# Generated by FakeRAM 2.0
VERSION 5.7 ;
BUSBITCHARS "[]" ;
PROPERTYDEFINITIONS
  MACRO width INTEGER ;
  MACRO depth INTEGER ;
  MACRO banks INTEGER ;
END PROPERTYDEFINITIONS
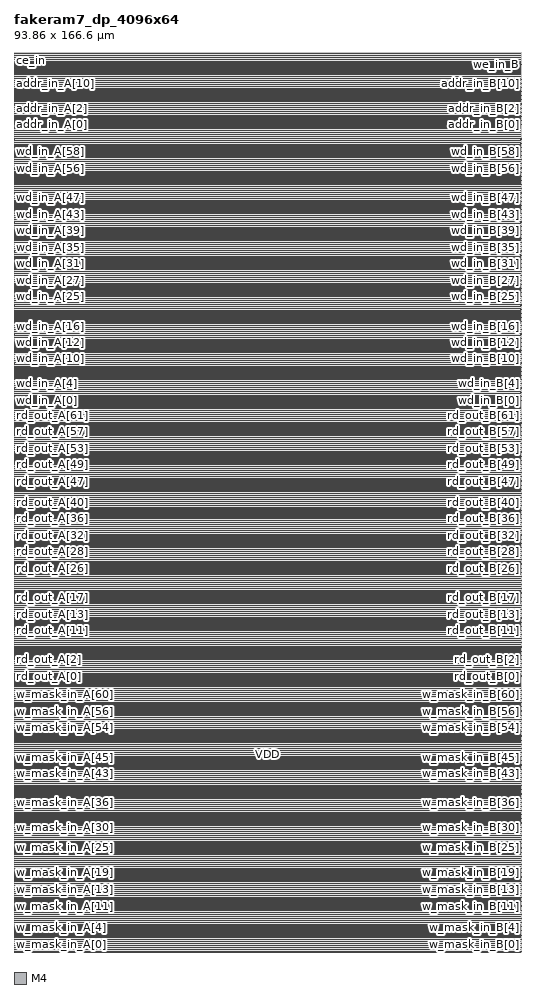
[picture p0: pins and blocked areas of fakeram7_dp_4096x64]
MACRO fakeram7_dp_4096x64
  PROPERTY width 64 ;
  PROPERTY depth 4096 ;
  PROPERTY banks 8 ;
  FOREIGN fakeram7_dp_4096x64 0 0 ;
  SYMMETRY X Y ;
  SIZE 93.860 BY 166.600 ;
  CLASS BLOCK ;
  PIN w_mask_in_A[0]
    DIRECTION INPUT ;
    USE SIGNAL ;
    SHAPE ABUTMENT ;
    PORT
      LAYER M4 ;
      RECT 0.000 0.048 0.024 0.072 ;
    END
  END w_mask_in_A[0]
  PIN w_mask_in_B[0]
    DIRECTION INPUT ;
    USE SIGNAL ;
    SHAPE ABUTMENT ;
    PORT
      LAYER M4 ;
      RECT 93.836 0.048 93.860 0.072 ;
    END
  END w_mask_in_B[0]
  PIN w_mask_in_A[1]
    DIRECTION INPUT ;
    USE SIGNAL ;
    SHAPE ABUTMENT ;
    PORT
      LAYER M4 ;
      RECT 0.000 0.816 0.024 0.840 ;
    END
  END w_mask_in_A[1]
  PIN w_mask_in_B[1]
    DIRECTION INPUT ;
    USE SIGNAL ;
    SHAPE ABUTMENT ;
    PORT
      LAYER M4 ;
      RECT 93.836 0.816 93.860 0.840 ;
    END
  END w_mask_in_B[1]
  PIN w_mask_in_A[2]
    DIRECTION INPUT ;
    USE SIGNAL ;
    SHAPE ABUTMENT ;
    PORT
      LAYER M4 ;
      RECT 0.000 1.584 0.024 1.608 ;
    END
  END w_mask_in_A[2]
  PIN w_mask_in_B[2]
    DIRECTION INPUT ;
    USE SIGNAL ;
    SHAPE ABUTMENT ;
    PORT
      LAYER M4 ;
      RECT 93.836 1.584 93.860 1.608 ;
    END
  END w_mask_in_B[2]
  PIN w_mask_in_A[3]
    DIRECTION INPUT ;
    USE SIGNAL ;
    SHAPE ABUTMENT ;
    PORT
      LAYER M4 ;
      RECT 0.000 2.352 0.024 2.376 ;
    END
  END w_mask_in_A[3]
  PIN w_mask_in_B[3]
    DIRECTION INPUT ;
    USE SIGNAL ;
    SHAPE ABUTMENT ;
    PORT
      LAYER M4 ;
      RECT 93.836 2.352 93.860 2.376 ;
    END
  END w_mask_in_B[3]
  PIN w_mask_in_A[4]
    DIRECTION INPUT ;
    USE SIGNAL ;
    SHAPE ABUTMENT ;
    PORT
      LAYER M4 ;
      RECT 0.000 3.120 0.024 3.144 ;
    END
  END w_mask_in_A[4]
  PIN w_mask_in_B[4]
    DIRECTION INPUT ;
    USE SIGNAL ;
    SHAPE ABUTMENT ;
    PORT
      LAYER M4 ;
      RECT 93.836 3.120 93.860 3.144 ;
    END
  END w_mask_in_B[4]
  PIN w_mask_in_A[5]
    DIRECTION INPUT ;
    USE SIGNAL ;
    SHAPE ABUTMENT ;
    PORT
      LAYER M4 ;
      RECT 0.000 3.888 0.024 3.912 ;
    END
  END w_mask_in_A[5]
  PIN w_mask_in_B[5]
    DIRECTION INPUT ;
    USE SIGNAL ;
    SHAPE ABUTMENT ;
    PORT
      LAYER M4 ;
      RECT 93.836 3.888 93.860 3.912 ;
    END
  END w_mask_in_B[5]
  PIN w_mask_in_A[6]
    DIRECTION INPUT ;
    USE SIGNAL ;
    SHAPE ABUTMENT ;
    PORT
      LAYER M4 ;
      RECT 0.000 4.656 0.024 4.680 ;
    END
  END w_mask_in_A[6]
  PIN w_mask_in_B[6]
    DIRECTION INPUT ;
    USE SIGNAL ;
    SHAPE ABUTMENT ;
    PORT
      LAYER M4 ;
      RECT 93.836 4.656 93.860 4.680 ;
    END
  END w_mask_in_B[6]
  PIN w_mask_in_A[7]
    DIRECTION INPUT ;
    USE SIGNAL ;
    SHAPE ABUTMENT ;
    PORT
      LAYER M4 ;
      RECT 0.000 5.424 0.024 5.448 ;
    END
  END w_mask_in_A[7]
  PIN w_mask_in_B[7]
    DIRECTION INPUT ;
    USE SIGNAL ;
    SHAPE ABUTMENT ;
    PORT
      LAYER M4 ;
      RECT 93.836 5.424 93.860 5.448 ;
    END
  END w_mask_in_B[7]
  PIN w_mask_in_A[8]
    DIRECTION INPUT ;
    USE SIGNAL ;
    SHAPE ABUTMENT ;
    PORT
      LAYER M4 ;
      RECT 0.000 6.192 0.024 6.216 ;
    END
  END w_mask_in_A[8]
  PIN w_mask_in_B[8]
    DIRECTION INPUT ;
    USE SIGNAL ;
    SHAPE ABUTMENT ;
    PORT
      LAYER M4 ;
      RECT 93.836 6.192 93.860 6.216 ;
    END
  END w_mask_in_B[8]
  PIN w_mask_in_A[9]
    DIRECTION INPUT ;
    USE SIGNAL ;
    SHAPE ABUTMENT ;
    PORT
      LAYER M4 ;
      RECT 0.000 6.960 0.024 6.984 ;
    END
  END w_mask_in_A[9]
  PIN w_mask_in_B[9]
    DIRECTION INPUT ;
    USE SIGNAL ;
    SHAPE ABUTMENT ;
    PORT
      LAYER M4 ;
      RECT 93.836 6.960 93.860 6.984 ;
    END
  END w_mask_in_B[9]
  PIN w_mask_in_A[10]
    DIRECTION INPUT ;
    USE SIGNAL ;
    SHAPE ABUTMENT ;
    PORT
      LAYER M4 ;
      RECT 0.000 7.728 0.024 7.752 ;
    END
  END w_mask_in_A[10]
  PIN w_mask_in_B[10]
    DIRECTION INPUT ;
    USE SIGNAL ;
    SHAPE ABUTMENT ;
    PORT
      LAYER M4 ;
      RECT 93.836 7.728 93.860 7.752 ;
    END
  END w_mask_in_B[10]
  PIN w_mask_in_A[11]
    DIRECTION INPUT ;
    USE SIGNAL ;
    SHAPE ABUTMENT ;
    PORT
      LAYER M4 ;
      RECT 0.000 8.496 0.024 8.520 ;
    END
  END w_mask_in_A[11]
  PIN w_mask_in_B[11]
    DIRECTION INPUT ;
    USE SIGNAL ;
    SHAPE ABUTMENT ;
    PORT
      LAYER M4 ;
      RECT 93.836 8.496 93.860 8.520 ;
    END
  END w_mask_in_B[11]
  PIN w_mask_in_A[12]
    DIRECTION INPUT ;
    USE SIGNAL ;
    SHAPE ABUTMENT ;
    PORT
      LAYER M4 ;
      RECT 0.000 9.264 0.024 9.288 ;
    END
  END w_mask_in_A[12]
  PIN w_mask_in_B[12]
    DIRECTION INPUT ;
    USE SIGNAL ;
    SHAPE ABUTMENT ;
    PORT
      LAYER M4 ;
      RECT 93.836 9.264 93.860 9.288 ;
    END
  END w_mask_in_B[12]
  PIN w_mask_in_A[13]
    DIRECTION INPUT ;
    USE SIGNAL ;
    SHAPE ABUTMENT ;
    PORT
      LAYER M4 ;
      RECT 0.000 10.032 0.024 10.056 ;
    END
  END w_mask_in_A[13]
  PIN w_mask_in_B[13]
    DIRECTION INPUT ;
    USE SIGNAL ;
    SHAPE ABUTMENT ;
    PORT
      LAYER M4 ;
      RECT 93.836 10.032 93.860 10.056 ;
    END
  END w_mask_in_B[13]
  PIN w_mask_in_A[14]
    DIRECTION INPUT ;
    USE SIGNAL ;
    SHAPE ABUTMENT ;
    PORT
      LAYER M4 ;
      RECT 0.000 10.800 0.024 10.824 ;
    END
  END w_mask_in_A[14]
  PIN w_mask_in_B[14]
    DIRECTION INPUT ;
    USE SIGNAL ;
    SHAPE ABUTMENT ;
    PORT
      LAYER M4 ;
      RECT 93.836 10.800 93.860 10.824 ;
    END
  END w_mask_in_B[14]
  PIN w_mask_in_A[15]
    DIRECTION INPUT ;
    USE SIGNAL ;
    SHAPE ABUTMENT ;
    PORT
      LAYER M4 ;
      RECT 0.000 11.568 0.024 11.592 ;
    END
  END w_mask_in_A[15]
  PIN w_mask_in_B[15]
    DIRECTION INPUT ;
    USE SIGNAL ;
    SHAPE ABUTMENT ;
    PORT
      LAYER M4 ;
      RECT 93.836 11.568 93.860 11.592 ;
    END
  END w_mask_in_B[15]
  PIN w_mask_in_A[16]
    DIRECTION INPUT ;
    USE SIGNAL ;
    SHAPE ABUTMENT ;
    PORT
      LAYER M4 ;
      RECT 0.000 12.336 0.024 12.360 ;
    END
  END w_mask_in_A[16]
  PIN w_mask_in_B[16]
    DIRECTION INPUT ;
    USE SIGNAL ;
    SHAPE ABUTMENT ;
    PORT
      LAYER M4 ;
      RECT 93.836 12.336 93.860 12.360 ;
    END
  END w_mask_in_B[16]
  PIN w_mask_in_A[17]
    DIRECTION INPUT ;
    USE SIGNAL ;
    SHAPE ABUTMENT ;
    PORT
      LAYER M4 ;
      RECT 0.000 13.104 0.024 13.128 ;
    END
  END w_mask_in_A[17]
  PIN w_mask_in_B[17]
    DIRECTION INPUT ;
    USE SIGNAL ;
    SHAPE ABUTMENT ;
    PORT
      LAYER M4 ;
      RECT 93.836 13.104 93.860 13.128 ;
    END
  END w_mask_in_B[17]
  PIN w_mask_in_A[18]
    DIRECTION INPUT ;
    USE SIGNAL ;
    SHAPE ABUTMENT ;
    PORT
      LAYER M4 ;
      RECT 0.000 13.872 0.024 13.896 ;
    END
  END w_mask_in_A[18]
  PIN w_mask_in_B[18]
    DIRECTION INPUT ;
    USE SIGNAL ;
    SHAPE ABUTMENT ;
    PORT
      LAYER M4 ;
      RECT 93.836 13.872 93.860 13.896 ;
    END
  END w_mask_in_B[18]
  PIN w_mask_in_A[19]
    DIRECTION INPUT ;
    USE SIGNAL ;
    SHAPE ABUTMENT ;
    PORT
      LAYER M4 ;
      RECT 0.000 14.640 0.024 14.664 ;
    END
  END w_mask_in_A[19]
  PIN w_mask_in_B[19]
    DIRECTION INPUT ;
    USE SIGNAL ;
    SHAPE ABUTMENT ;
    PORT
      LAYER M4 ;
      RECT 93.836 14.640 93.860 14.664 ;
    END
  END w_mask_in_B[19]
  PIN w_mask_in_A[20]
    DIRECTION INPUT ;
    USE SIGNAL ;
    SHAPE ABUTMENT ;
    PORT
      LAYER M4 ;
      RECT 0.000 15.408 0.024 15.432 ;
    END
  END w_mask_in_A[20]
  PIN w_mask_in_B[20]
    DIRECTION INPUT ;
    USE SIGNAL ;
    SHAPE ABUTMENT ;
    PORT
      LAYER M4 ;
      RECT 93.836 15.408 93.860 15.432 ;
    END
  END w_mask_in_B[20]
  PIN w_mask_in_A[21]
    DIRECTION INPUT ;
    USE SIGNAL ;
    SHAPE ABUTMENT ;
    PORT
      LAYER M4 ;
      RECT 0.000 16.176 0.024 16.200 ;
    END
  END w_mask_in_A[21]
  PIN w_mask_in_B[21]
    DIRECTION INPUT ;
    USE SIGNAL ;
    SHAPE ABUTMENT ;
    PORT
      LAYER M4 ;
      RECT 93.836 16.176 93.860 16.200 ;
    END
  END w_mask_in_B[21]
  PIN w_mask_in_A[22]
    DIRECTION INPUT ;
    USE SIGNAL ;
    SHAPE ABUTMENT ;
    PORT
      LAYER M4 ;
      RECT 0.000 16.944 0.024 16.968 ;
    END
  END w_mask_in_A[22]
  PIN w_mask_in_B[22]
    DIRECTION INPUT ;
    USE SIGNAL ;
    SHAPE ABUTMENT ;
    PORT
      LAYER M4 ;
      RECT 93.836 16.944 93.860 16.968 ;
    END
  END w_mask_in_B[22]
  PIN w_mask_in_A[23]
    DIRECTION INPUT ;
    USE SIGNAL ;
    SHAPE ABUTMENT ;
    PORT
      LAYER M4 ;
      RECT 0.000 17.712 0.024 17.736 ;
    END
  END w_mask_in_A[23]
  PIN w_mask_in_B[23]
    DIRECTION INPUT ;
    USE SIGNAL ;
    SHAPE ABUTMENT ;
    PORT
      LAYER M4 ;
      RECT 93.836 17.712 93.860 17.736 ;
    END
  END w_mask_in_B[23]
  PIN w_mask_in_A[24]
    DIRECTION INPUT ;
    USE SIGNAL ;
    SHAPE ABUTMENT ;
    PORT
      LAYER M4 ;
      RECT 0.000 18.480 0.024 18.504 ;
    END
  END w_mask_in_A[24]
  PIN w_mask_in_B[24]
    DIRECTION INPUT ;
    USE SIGNAL ;
    SHAPE ABUTMENT ;
    PORT
      LAYER M4 ;
      RECT 93.836 18.480 93.860 18.504 ;
    END
  END w_mask_in_B[24]
  PIN w_mask_in_A[25]
    DIRECTION INPUT ;
    USE SIGNAL ;
    SHAPE ABUTMENT ;
    PORT
      LAYER M4 ;
      RECT 0.000 19.248 0.024 19.272 ;
    END
  END w_mask_in_A[25]
  PIN w_mask_in_B[25]
    DIRECTION INPUT ;
    USE SIGNAL ;
    SHAPE ABUTMENT ;
    PORT
      LAYER M4 ;
      RECT 93.836 19.248 93.860 19.272 ;
    END
  END w_mask_in_B[25]
  PIN w_mask_in_A[26]
    DIRECTION INPUT ;
    USE SIGNAL ;
    SHAPE ABUTMENT ;
    PORT
      LAYER M4 ;
      RECT 0.000 20.016 0.024 20.040 ;
    END
  END w_mask_in_A[26]
  PIN w_mask_in_B[26]
    DIRECTION INPUT ;
    USE SIGNAL ;
    SHAPE ABUTMENT ;
    PORT
      LAYER M4 ;
      RECT 93.836 20.016 93.860 20.040 ;
    END
  END w_mask_in_B[26]
  PIN w_mask_in_A[27]
    DIRECTION INPUT ;
    USE SIGNAL ;
    SHAPE ABUTMENT ;
    PORT
      LAYER M4 ;
      RECT 0.000 20.784 0.024 20.808 ;
    END
  END w_mask_in_A[27]
  PIN w_mask_in_B[27]
    DIRECTION INPUT ;
    USE SIGNAL ;
    SHAPE ABUTMENT ;
    PORT
      LAYER M4 ;
      RECT 93.836 20.784 93.860 20.808 ;
    END
  END w_mask_in_B[27]
  PIN w_mask_in_A[28]
    DIRECTION INPUT ;
    USE SIGNAL ;
    SHAPE ABUTMENT ;
    PORT
      LAYER M4 ;
      RECT 0.000 21.552 0.024 21.576 ;
    END
  END w_mask_in_A[28]
  PIN w_mask_in_B[28]
    DIRECTION INPUT ;
    USE SIGNAL ;
    SHAPE ABUTMENT ;
    PORT
      LAYER M4 ;
      RECT 93.836 21.552 93.860 21.576 ;
    END
  END w_mask_in_B[28]
  PIN w_mask_in_A[29]
    DIRECTION INPUT ;
    USE SIGNAL ;
    SHAPE ABUTMENT ;
    PORT
      LAYER M4 ;
      RECT 0.000 22.320 0.024 22.344 ;
    END
  END w_mask_in_A[29]
  PIN w_mask_in_B[29]
    DIRECTION INPUT ;
    USE SIGNAL ;
    SHAPE ABUTMENT ;
    PORT
      LAYER M4 ;
      RECT 93.836 22.320 93.860 22.344 ;
    END
  END w_mask_in_B[29]
  PIN w_mask_in_A[30]
    DIRECTION INPUT ;
    USE SIGNAL ;
    SHAPE ABUTMENT ;
    PORT
      LAYER M4 ;
      RECT 0.000 23.088 0.024 23.112 ;
    END
  END w_mask_in_A[30]
  PIN w_mask_in_B[30]
    DIRECTION INPUT ;
    USE SIGNAL ;
    SHAPE ABUTMENT ;
    PORT
      LAYER M4 ;
      RECT 93.836 23.088 93.860 23.112 ;
    END
  END w_mask_in_B[30]
  PIN w_mask_in_A[31]
    DIRECTION INPUT ;
    USE SIGNAL ;
    SHAPE ABUTMENT ;
    PORT
      LAYER M4 ;
      RECT 0.000 23.856 0.024 23.880 ;
    END
  END w_mask_in_A[31]
  PIN w_mask_in_B[31]
    DIRECTION INPUT ;
    USE SIGNAL ;
    SHAPE ABUTMENT ;
    PORT
      LAYER M4 ;
      RECT 93.836 23.856 93.860 23.880 ;
    END
  END w_mask_in_B[31]
  PIN w_mask_in_A[32]
    DIRECTION INPUT ;
    USE SIGNAL ;
    SHAPE ABUTMENT ;
    PORT
      LAYER M4 ;
      RECT 0.000 24.624 0.024 24.648 ;
    END
  END w_mask_in_A[32]
  PIN w_mask_in_B[32]
    DIRECTION INPUT ;
    USE SIGNAL ;
    SHAPE ABUTMENT ;
    PORT
      LAYER M4 ;
      RECT 93.836 24.624 93.860 24.648 ;
    END
  END w_mask_in_B[32]
  PIN w_mask_in_A[33]
    DIRECTION INPUT ;
    USE SIGNAL ;
    SHAPE ABUTMENT ;
    PORT
      LAYER M4 ;
      RECT 0.000 25.392 0.024 25.416 ;
    END
  END w_mask_in_A[33]
  PIN w_mask_in_B[33]
    DIRECTION INPUT ;
    USE SIGNAL ;
    SHAPE ABUTMENT ;
    PORT
      LAYER M4 ;
      RECT 93.836 25.392 93.860 25.416 ;
    END
  END w_mask_in_B[33]
  PIN w_mask_in_A[34]
    DIRECTION INPUT ;
    USE SIGNAL ;
    SHAPE ABUTMENT ;
    PORT
      LAYER M4 ;
      RECT 0.000 26.160 0.024 26.184 ;
    END
  END w_mask_in_A[34]
  PIN w_mask_in_B[34]
    DIRECTION INPUT ;
    USE SIGNAL ;
    SHAPE ABUTMENT ;
    PORT
      LAYER M4 ;
      RECT 93.836 26.160 93.860 26.184 ;
    END
  END w_mask_in_B[34]
  PIN w_mask_in_A[35]
    DIRECTION INPUT ;
    USE SIGNAL ;
    SHAPE ABUTMENT ;
    PORT
      LAYER M4 ;
      RECT 0.000 26.928 0.024 26.952 ;
    END
  END w_mask_in_A[35]
  PIN w_mask_in_B[35]
    DIRECTION INPUT ;
    USE SIGNAL ;
    SHAPE ABUTMENT ;
    PORT
      LAYER M4 ;
      RECT 93.836 26.928 93.860 26.952 ;
    END
  END w_mask_in_B[35]
  PIN w_mask_in_A[36]
    DIRECTION INPUT ;
    USE SIGNAL ;
    SHAPE ABUTMENT ;
    PORT
      LAYER M4 ;
      RECT 0.000 27.696 0.024 27.720 ;
    END
  END w_mask_in_A[36]
  PIN w_mask_in_B[36]
    DIRECTION INPUT ;
    USE SIGNAL ;
    SHAPE ABUTMENT ;
    PORT
      LAYER M4 ;
      RECT 93.836 27.696 93.860 27.720 ;
    END
  END w_mask_in_B[36]
  PIN w_mask_in_A[37]
    DIRECTION INPUT ;
    USE SIGNAL ;
    SHAPE ABUTMENT ;
    PORT
      LAYER M4 ;
      RECT 0.000 28.464 0.024 28.488 ;
    END
  END w_mask_in_A[37]
  PIN w_mask_in_B[37]
    DIRECTION INPUT ;
    USE SIGNAL ;
    SHAPE ABUTMENT ;
    PORT
      LAYER M4 ;
      RECT 93.836 28.464 93.860 28.488 ;
    END
  END w_mask_in_B[37]
  PIN w_mask_in_A[38]
    DIRECTION INPUT ;
    USE SIGNAL ;
    SHAPE ABUTMENT ;
    PORT
      LAYER M4 ;
      RECT 0.000 29.232 0.024 29.256 ;
    END
  END w_mask_in_A[38]
  PIN w_mask_in_B[38]
    DIRECTION INPUT ;
    USE SIGNAL ;
    SHAPE ABUTMENT ;
    PORT
      LAYER M4 ;
      RECT 93.836 29.232 93.860 29.256 ;
    END
  END w_mask_in_B[38]
  PIN w_mask_in_A[39]
    DIRECTION INPUT ;
    USE SIGNAL ;
    SHAPE ABUTMENT ;
    PORT
      LAYER M4 ;
      RECT 0.000 30.000 0.024 30.024 ;
    END
  END w_mask_in_A[39]
  PIN w_mask_in_B[39]
    DIRECTION INPUT ;
    USE SIGNAL ;
    SHAPE ABUTMENT ;
    PORT
      LAYER M4 ;
      RECT 93.836 30.000 93.860 30.024 ;
    END
  END w_mask_in_B[39]
  PIN w_mask_in_A[40]
    DIRECTION INPUT ;
    USE SIGNAL ;
    SHAPE ABUTMENT ;
    PORT
      LAYER M4 ;
      RECT 0.000 30.768 0.024 30.792 ;
    END
  END w_mask_in_A[40]
  PIN w_mask_in_B[40]
    DIRECTION INPUT ;
    USE SIGNAL ;
    SHAPE ABUTMENT ;
    PORT
      LAYER M4 ;
      RECT 93.836 30.768 93.860 30.792 ;
    END
  END w_mask_in_B[40]
  PIN w_mask_in_A[41]
    DIRECTION INPUT ;
    USE SIGNAL ;
    SHAPE ABUTMENT ;
    PORT
      LAYER M4 ;
      RECT 0.000 31.536 0.024 31.560 ;
    END
  END w_mask_in_A[41]
  PIN w_mask_in_B[41]
    DIRECTION INPUT ;
    USE SIGNAL ;
    SHAPE ABUTMENT ;
    PORT
      LAYER M4 ;
      RECT 93.836 31.536 93.860 31.560 ;
    END
  END w_mask_in_B[41]
  PIN w_mask_in_A[42]
    DIRECTION INPUT ;
    USE SIGNAL ;
    SHAPE ABUTMENT ;
    PORT
      LAYER M4 ;
      RECT 0.000 32.304 0.024 32.328 ;
    END
  END w_mask_in_A[42]
  PIN w_mask_in_B[42]
    DIRECTION INPUT ;
    USE SIGNAL ;
    SHAPE ABUTMENT ;
    PORT
      LAYER M4 ;
      RECT 93.836 32.304 93.860 32.328 ;
    END
  END w_mask_in_B[42]
  PIN w_mask_in_A[43]
    DIRECTION INPUT ;
    USE SIGNAL ;
    SHAPE ABUTMENT ;
    PORT
      LAYER M4 ;
      RECT 0.000 33.072 0.024 33.096 ;
    END
  END w_mask_in_A[43]
  PIN w_mask_in_B[43]
    DIRECTION INPUT ;
    USE SIGNAL ;
    SHAPE ABUTMENT ;
    PORT
      LAYER M4 ;
      RECT 93.836 33.072 93.860 33.096 ;
    END
  END w_mask_in_B[43]
  PIN w_mask_in_A[44]
    DIRECTION INPUT ;
    USE SIGNAL ;
    SHAPE ABUTMENT ;
    PORT
      LAYER M4 ;
      RECT 0.000 33.840 0.024 33.864 ;
    END
  END w_mask_in_A[44]
  PIN w_mask_in_B[44]
    DIRECTION INPUT ;
    USE SIGNAL ;
    SHAPE ABUTMENT ;
    PORT
      LAYER M4 ;
      RECT 93.836 33.840 93.860 33.864 ;
    END
  END w_mask_in_B[44]
  PIN w_mask_in_A[45]
    DIRECTION INPUT ;
    USE SIGNAL ;
    SHAPE ABUTMENT ;
    PORT
      LAYER M4 ;
      RECT 0.000 34.608 0.024 34.632 ;
    END
  END w_mask_in_A[45]
  PIN w_mask_in_B[45]
    DIRECTION INPUT ;
    USE SIGNAL ;
    SHAPE ABUTMENT ;
    PORT
      LAYER M4 ;
      RECT 93.836 34.608 93.860 34.632 ;
    END
  END w_mask_in_B[45]
  PIN w_mask_in_A[46]
    DIRECTION INPUT ;
    USE SIGNAL ;
    SHAPE ABUTMENT ;
    PORT
      LAYER M4 ;
      RECT 0.000 35.376 0.024 35.400 ;
    END
  END w_mask_in_A[46]
  PIN w_mask_in_B[46]
    DIRECTION INPUT ;
    USE SIGNAL ;
    SHAPE ABUTMENT ;
    PORT
      LAYER M4 ;
      RECT 93.836 35.376 93.860 35.400 ;
    END
  END w_mask_in_B[46]
  PIN w_mask_in_A[47]
    DIRECTION INPUT ;
    USE SIGNAL ;
    SHAPE ABUTMENT ;
    PORT
      LAYER M4 ;
      RECT 0.000 36.144 0.024 36.168 ;
    END
  END w_mask_in_A[47]
  PIN w_mask_in_B[47]
    DIRECTION INPUT ;
    USE SIGNAL ;
    SHAPE ABUTMENT ;
    PORT
      LAYER M4 ;
      RECT 93.836 36.144 93.860 36.168 ;
    END
  END w_mask_in_B[47]
  PIN w_mask_in_A[48]
    DIRECTION INPUT ;
    USE SIGNAL ;
    SHAPE ABUTMENT ;
    PORT
      LAYER M4 ;
      RECT 0.000 36.912 0.024 36.936 ;
    END
  END w_mask_in_A[48]
  PIN w_mask_in_B[48]
    DIRECTION INPUT ;
    USE SIGNAL ;
    SHAPE ABUTMENT ;
    PORT
      LAYER M4 ;
      RECT 93.836 36.912 93.860 36.936 ;
    END
  END w_mask_in_B[48]
  PIN w_mask_in_A[49]
    DIRECTION INPUT ;
    USE SIGNAL ;
    SHAPE ABUTMENT ;
    PORT
      LAYER M4 ;
      RECT 0.000 37.680 0.024 37.704 ;
    END
  END w_mask_in_A[49]
  PIN w_mask_in_B[49]
    DIRECTION INPUT ;
    USE SIGNAL ;
    SHAPE ABUTMENT ;
    PORT
      LAYER M4 ;
      RECT 93.836 37.680 93.860 37.704 ;
    END
  END w_mask_in_B[49]
  PIN w_mask_in_A[50]
    DIRECTION INPUT ;
    USE SIGNAL ;
    SHAPE ABUTMENT ;
    PORT
      LAYER M4 ;
      RECT 0.000 38.448 0.024 38.472 ;
    END
  END w_mask_in_A[50]
  PIN w_mask_in_B[50]
    DIRECTION INPUT ;
    USE SIGNAL ;
    SHAPE ABUTMENT ;
    PORT
      LAYER M4 ;
      RECT 93.836 38.448 93.860 38.472 ;
    END
  END w_mask_in_B[50]
  PIN w_mask_in_A[51]
    DIRECTION INPUT ;
    USE SIGNAL ;
    SHAPE ABUTMENT ;
    PORT
      LAYER M4 ;
      RECT 0.000 39.216 0.024 39.240 ;
    END
  END w_mask_in_A[51]
  PIN w_mask_in_B[51]
    DIRECTION INPUT ;
    USE SIGNAL ;
    SHAPE ABUTMENT ;
    PORT
      LAYER M4 ;
      RECT 93.836 39.216 93.860 39.240 ;
    END
  END w_mask_in_B[51]
  PIN w_mask_in_A[52]
    DIRECTION INPUT ;
    USE SIGNAL ;
    SHAPE ABUTMENT ;
    PORT
      LAYER M4 ;
      RECT 0.000 39.984 0.024 40.008 ;
    END
  END w_mask_in_A[52]
  PIN w_mask_in_B[52]
    DIRECTION INPUT ;
    USE SIGNAL ;
    SHAPE ABUTMENT ;
    PORT
      LAYER M4 ;
      RECT 93.836 39.984 93.860 40.008 ;
    END
  END w_mask_in_B[52]
  PIN w_mask_in_A[53]
    DIRECTION INPUT ;
    USE SIGNAL ;
    SHAPE ABUTMENT ;
    PORT
      LAYER M4 ;
      RECT 0.000 40.752 0.024 40.776 ;
    END
  END w_mask_in_A[53]
  PIN w_mask_in_B[53]
    DIRECTION INPUT ;
    USE SIGNAL ;
    SHAPE ABUTMENT ;
    PORT
      LAYER M4 ;
      RECT 93.836 40.752 93.860 40.776 ;
    END
  END w_mask_in_B[53]
  PIN w_mask_in_A[54]
    DIRECTION INPUT ;
    USE SIGNAL ;
    SHAPE ABUTMENT ;
    PORT
      LAYER M4 ;
      RECT 0.000 41.520 0.024 41.544 ;
    END
  END w_mask_in_A[54]
  PIN w_mask_in_B[54]
    DIRECTION INPUT ;
    USE SIGNAL ;
    SHAPE ABUTMENT ;
    PORT
      LAYER M4 ;
      RECT 93.836 41.520 93.860 41.544 ;
    END
  END w_mask_in_B[54]
  PIN w_mask_in_A[55]
    DIRECTION INPUT ;
    USE SIGNAL ;
    SHAPE ABUTMENT ;
    PORT
      LAYER M4 ;
      RECT 0.000 42.288 0.024 42.312 ;
    END
  END w_mask_in_A[55]
  PIN w_mask_in_B[55]
    DIRECTION INPUT ;
    USE SIGNAL ;
    SHAPE ABUTMENT ;
    PORT
      LAYER M4 ;
      RECT 93.836 42.288 93.860 42.312 ;
    END
  END w_mask_in_B[55]
  PIN w_mask_in_A[56]
    DIRECTION INPUT ;
    USE SIGNAL ;
    SHAPE ABUTMENT ;
    PORT
      LAYER M4 ;
      RECT 0.000 43.056 0.024 43.080 ;
    END
  END w_mask_in_A[56]
  PIN w_mask_in_B[56]
    DIRECTION INPUT ;
    USE SIGNAL ;
    SHAPE ABUTMENT ;
    PORT
      LAYER M4 ;
      RECT 93.836 43.056 93.860 43.080 ;
    END
  END w_mask_in_B[56]
  PIN w_mask_in_A[57]
    DIRECTION INPUT ;
    USE SIGNAL ;
    SHAPE ABUTMENT ;
    PORT
      LAYER M4 ;
      RECT 0.000 43.824 0.024 43.848 ;
    END
  END w_mask_in_A[57]
  PIN w_mask_in_B[57]
    DIRECTION INPUT ;
    USE SIGNAL ;
    SHAPE ABUTMENT ;
    PORT
      LAYER M4 ;
      RECT 93.836 43.824 93.860 43.848 ;
    END
  END w_mask_in_B[57]
  PIN w_mask_in_A[58]
    DIRECTION INPUT ;
    USE SIGNAL ;
    SHAPE ABUTMENT ;
    PORT
      LAYER M4 ;
      RECT 0.000 44.592 0.024 44.616 ;
    END
  END w_mask_in_A[58]
  PIN w_mask_in_B[58]
    DIRECTION INPUT ;
    USE SIGNAL ;
    SHAPE ABUTMENT ;
    PORT
      LAYER M4 ;
      RECT 93.836 44.592 93.860 44.616 ;
    END
  END w_mask_in_B[58]
  PIN w_mask_in_A[59]
    DIRECTION INPUT ;
    USE SIGNAL ;
    SHAPE ABUTMENT ;
    PORT
      LAYER M4 ;
      RECT 0.000 45.360 0.024 45.384 ;
    END
  END w_mask_in_A[59]
  PIN w_mask_in_B[59]
    DIRECTION INPUT ;
    USE SIGNAL ;
    SHAPE ABUTMENT ;
    PORT
      LAYER M4 ;
      RECT 93.836 45.360 93.860 45.384 ;
    END
  END w_mask_in_B[59]
  PIN w_mask_in_A[60]
    DIRECTION INPUT ;
    USE SIGNAL ;
    SHAPE ABUTMENT ;
    PORT
      LAYER M4 ;
      RECT 0.000 46.128 0.024 46.152 ;
    END
  END w_mask_in_A[60]
  PIN w_mask_in_B[60]
    DIRECTION INPUT ;
    USE SIGNAL ;
    SHAPE ABUTMENT ;
    PORT
      LAYER M4 ;
      RECT 93.836 46.128 93.860 46.152 ;
    END
  END w_mask_in_B[60]
  PIN w_mask_in_A[61]
    DIRECTION INPUT ;
    USE SIGNAL ;
    SHAPE ABUTMENT ;
    PORT
      LAYER M4 ;
      RECT 0.000 46.896 0.024 46.920 ;
    END
  END w_mask_in_A[61]
  PIN w_mask_in_B[61]
    DIRECTION INPUT ;
    USE SIGNAL ;
    SHAPE ABUTMENT ;
    PORT
      LAYER M4 ;
      RECT 93.836 46.896 93.860 46.920 ;
    END
  END w_mask_in_B[61]
  PIN w_mask_in_A[62]
    DIRECTION INPUT ;
    USE SIGNAL ;
    SHAPE ABUTMENT ;
    PORT
      LAYER M4 ;
      RECT 0.000 47.664 0.024 47.688 ;
    END
  END w_mask_in_A[62]
  PIN w_mask_in_B[62]
    DIRECTION INPUT ;
    USE SIGNAL ;
    SHAPE ABUTMENT ;
    PORT
      LAYER M4 ;
      RECT 93.836 47.664 93.860 47.688 ;
    END
  END w_mask_in_B[62]
  PIN w_mask_in_A[63]
    DIRECTION INPUT ;
    USE SIGNAL ;
    SHAPE ABUTMENT ;
    PORT
      LAYER M4 ;
      RECT 0.000 48.432 0.024 48.456 ;
    END
  END w_mask_in_A[63]
  PIN w_mask_in_B[63]
    DIRECTION INPUT ;
    USE SIGNAL ;
    SHAPE ABUTMENT ;
    PORT
      LAYER M4 ;
      RECT 93.836 48.432 93.860 48.456 ;
    END
  END w_mask_in_B[63]
  PIN rd_out_A[0]
    DIRECTION OUTPUT ;
    USE SIGNAL ;
    SHAPE ABUTMENT ;
    PORT
      LAYER M4 ;
      RECT 0.000 51.072 0.024 51.096 ;
    END
  END rd_out_A[0]
  PIN rd_out_B[0]
    DIRECTION OUTPUT ;
    USE SIGNAL ;
    SHAPE ABUTMENT ;
    PORT
      LAYER M4 ;
      RECT 93.836 51.072 93.860 51.096 ;
    END
  END rd_out_B[0]
  PIN rd_out_A[1]
    DIRECTION OUTPUT ;
    USE SIGNAL ;
    SHAPE ABUTMENT ;
    PORT
      LAYER M4 ;
      RECT 0.000 51.840 0.024 51.864 ;
    END
  END rd_out_A[1]
  PIN rd_out_B[1]
    DIRECTION OUTPUT ;
    USE SIGNAL ;
    SHAPE ABUTMENT ;
    PORT
      LAYER M4 ;
      RECT 93.836 51.840 93.860 51.864 ;
    END
  END rd_out_B[1]
  PIN rd_out_A[2]
    DIRECTION OUTPUT ;
    USE SIGNAL ;
    SHAPE ABUTMENT ;
    PORT
      LAYER M4 ;
      RECT 0.000 52.608 0.024 52.632 ;
    END
  END rd_out_A[2]
  PIN rd_out_B[2]
    DIRECTION OUTPUT ;
    USE SIGNAL ;
    SHAPE ABUTMENT ;
    PORT
      LAYER M4 ;
      RECT 93.836 52.608 93.860 52.632 ;
    END
  END rd_out_B[2]
  PIN rd_out_A[3]
    DIRECTION OUTPUT ;
    USE SIGNAL ;
    SHAPE ABUTMENT ;
    PORT
      LAYER M4 ;
      RECT 0.000 53.376 0.024 53.400 ;
    END
  END rd_out_A[3]
  PIN rd_out_B[3]
    DIRECTION OUTPUT ;
    USE SIGNAL ;
    SHAPE ABUTMENT ;
    PORT
      LAYER M4 ;
      RECT 93.836 53.376 93.860 53.400 ;
    END
  END rd_out_B[3]
  PIN rd_out_A[4]
    DIRECTION OUTPUT ;
    USE SIGNAL ;
    SHAPE ABUTMENT ;
    PORT
      LAYER M4 ;
      RECT 0.000 54.144 0.024 54.168 ;
    END
  END rd_out_A[4]
  PIN rd_out_B[4]
    DIRECTION OUTPUT ;
    USE SIGNAL ;
    SHAPE ABUTMENT ;
    PORT
      LAYER M4 ;
      RECT 93.836 54.144 93.860 54.168 ;
    END
  END rd_out_B[4]
  PIN rd_out_A[5]
    DIRECTION OUTPUT ;
    USE SIGNAL ;
    SHAPE ABUTMENT ;
    PORT
      LAYER M4 ;
      RECT 0.000 54.912 0.024 54.936 ;
    END
  END rd_out_A[5]
  PIN rd_out_B[5]
    DIRECTION OUTPUT ;
    USE SIGNAL ;
    SHAPE ABUTMENT ;
    PORT
      LAYER M4 ;
      RECT 93.836 54.912 93.860 54.936 ;
    END
  END rd_out_B[5]
  PIN rd_out_A[6]
    DIRECTION OUTPUT ;
    USE SIGNAL ;
    SHAPE ABUTMENT ;
    PORT
      LAYER M4 ;
      RECT 0.000 55.680 0.024 55.704 ;
    END
  END rd_out_A[6]
  PIN rd_out_B[6]
    DIRECTION OUTPUT ;
    USE SIGNAL ;
    SHAPE ABUTMENT ;
    PORT
      LAYER M4 ;
      RECT 93.836 55.680 93.860 55.704 ;
    END
  END rd_out_B[6]
  PIN rd_out_A[7]
    DIRECTION OUTPUT ;
    USE SIGNAL ;
    SHAPE ABUTMENT ;
    PORT
      LAYER M4 ;
      RECT 0.000 56.448 0.024 56.472 ;
    END
  END rd_out_A[7]
  PIN rd_out_B[7]
    DIRECTION OUTPUT ;
    USE SIGNAL ;
    SHAPE ABUTMENT ;
    PORT
      LAYER M4 ;
      RECT 93.836 56.448 93.860 56.472 ;
    END
  END rd_out_B[7]
  PIN rd_out_A[8]
    DIRECTION OUTPUT ;
    USE SIGNAL ;
    SHAPE ABUTMENT ;
    PORT
      LAYER M4 ;
      RECT 0.000 57.216 0.024 57.240 ;
    END
  END rd_out_A[8]
  PIN rd_out_B[8]
    DIRECTION OUTPUT ;
    USE SIGNAL ;
    SHAPE ABUTMENT ;
    PORT
      LAYER M4 ;
      RECT 93.836 57.216 93.860 57.240 ;
    END
  END rd_out_B[8]
  PIN rd_out_A[9]
    DIRECTION OUTPUT ;
    USE SIGNAL ;
    SHAPE ABUTMENT ;
    PORT
      LAYER M4 ;
      RECT 0.000 57.984 0.024 58.008 ;
    END
  END rd_out_A[9]
  PIN rd_out_B[9]
    DIRECTION OUTPUT ;
    USE SIGNAL ;
    SHAPE ABUTMENT ;
    PORT
      LAYER M4 ;
      RECT 93.836 57.984 93.860 58.008 ;
    END
  END rd_out_B[9]
  PIN rd_out_A[10]
    DIRECTION OUTPUT ;
    USE SIGNAL ;
    SHAPE ABUTMENT ;
    PORT
      LAYER M4 ;
      RECT 0.000 58.752 0.024 58.776 ;
    END
  END rd_out_A[10]
  PIN rd_out_B[10]
    DIRECTION OUTPUT ;
    USE SIGNAL ;
    SHAPE ABUTMENT ;
    PORT
      LAYER M4 ;
      RECT 93.836 58.752 93.860 58.776 ;
    END
  END rd_out_B[10]
  PIN rd_out_A[11]
    DIRECTION OUTPUT ;
    USE SIGNAL ;
    SHAPE ABUTMENT ;
    PORT
      LAYER M4 ;
      RECT 0.000 59.520 0.024 59.544 ;
    END
  END rd_out_A[11]
  PIN rd_out_B[11]
    DIRECTION OUTPUT ;
    USE SIGNAL ;
    SHAPE ABUTMENT ;
    PORT
      LAYER M4 ;
      RECT 93.836 59.520 93.860 59.544 ;
    END
  END rd_out_B[11]
  PIN rd_out_A[12]
    DIRECTION OUTPUT ;
    USE SIGNAL ;
    SHAPE ABUTMENT ;
    PORT
      LAYER M4 ;
      RECT 0.000 60.288 0.024 60.312 ;
    END
  END rd_out_A[12]
  PIN rd_out_B[12]
    DIRECTION OUTPUT ;
    USE SIGNAL ;
    SHAPE ABUTMENT ;
    PORT
      LAYER M4 ;
      RECT 93.836 60.288 93.860 60.312 ;
    END
  END rd_out_B[12]
  PIN rd_out_A[13]
    DIRECTION OUTPUT ;
    USE SIGNAL ;
    SHAPE ABUTMENT ;
    PORT
      LAYER M4 ;
      RECT 0.000 61.056 0.024 61.080 ;
    END
  END rd_out_A[13]
  PIN rd_out_B[13]
    DIRECTION OUTPUT ;
    USE SIGNAL ;
    SHAPE ABUTMENT ;
    PORT
      LAYER M4 ;
      RECT 93.836 61.056 93.860 61.080 ;
    END
  END rd_out_B[13]
  PIN rd_out_A[14]
    DIRECTION OUTPUT ;
    USE SIGNAL ;
    SHAPE ABUTMENT ;
    PORT
      LAYER M4 ;
      RECT 0.000 61.824 0.024 61.848 ;
    END
  END rd_out_A[14]
  PIN rd_out_B[14]
    DIRECTION OUTPUT ;
    USE SIGNAL ;
    SHAPE ABUTMENT ;
    PORT
      LAYER M4 ;
      RECT 93.836 61.824 93.860 61.848 ;
    END
  END rd_out_B[14]
  PIN rd_out_A[15]
    DIRECTION OUTPUT ;
    USE SIGNAL ;
    SHAPE ABUTMENT ;
    PORT
      LAYER M4 ;
      RECT 0.000 62.592 0.024 62.616 ;
    END
  END rd_out_A[15]
  PIN rd_out_B[15]
    DIRECTION OUTPUT ;
    USE SIGNAL ;
    SHAPE ABUTMENT ;
    PORT
      LAYER M4 ;
      RECT 93.836 62.592 93.860 62.616 ;
    END
  END rd_out_B[15]
  PIN rd_out_A[16]
    DIRECTION OUTPUT ;
    USE SIGNAL ;
    SHAPE ABUTMENT ;
    PORT
      LAYER M4 ;
      RECT 0.000 63.360 0.024 63.384 ;
    END
  END rd_out_A[16]
  PIN rd_out_B[16]
    DIRECTION OUTPUT ;
    USE SIGNAL ;
    SHAPE ABUTMENT ;
    PORT
      LAYER M4 ;
      RECT 93.836 63.360 93.860 63.384 ;
    END
  END rd_out_B[16]
  PIN rd_out_A[17]
    DIRECTION OUTPUT ;
    USE SIGNAL ;
    SHAPE ABUTMENT ;
    PORT
      LAYER M4 ;
      RECT 0.000 64.128 0.024 64.152 ;
    END
  END rd_out_A[17]
  PIN rd_out_B[17]
    DIRECTION OUTPUT ;
    USE SIGNAL ;
    SHAPE ABUTMENT ;
    PORT
      LAYER M4 ;
      RECT 93.836 64.128 93.860 64.152 ;
    END
  END rd_out_B[17]
  PIN rd_out_A[18]
    DIRECTION OUTPUT ;
    USE SIGNAL ;
    SHAPE ABUTMENT ;
    PORT
      LAYER M4 ;
      RECT 0.000 64.896 0.024 64.920 ;
    END
  END rd_out_A[18]
  PIN rd_out_B[18]
    DIRECTION OUTPUT ;
    USE SIGNAL ;
    SHAPE ABUTMENT ;
    PORT
      LAYER M4 ;
      RECT 93.836 64.896 93.860 64.920 ;
    END
  END rd_out_B[18]
  PIN rd_out_A[19]
    DIRECTION OUTPUT ;
    USE SIGNAL ;
    SHAPE ABUTMENT ;
    PORT
      LAYER M4 ;
      RECT 0.000 65.664 0.024 65.688 ;
    END
  END rd_out_A[19]
  PIN rd_out_B[19]
    DIRECTION OUTPUT ;
    USE SIGNAL ;
    SHAPE ABUTMENT ;
    PORT
      LAYER M4 ;
      RECT 93.836 65.664 93.860 65.688 ;
    END
  END rd_out_B[19]
  PIN rd_out_A[20]
    DIRECTION OUTPUT ;
    USE SIGNAL ;
    SHAPE ABUTMENT ;
    PORT
      LAYER M4 ;
      RECT 0.000 66.432 0.024 66.456 ;
    END
  END rd_out_A[20]
  PIN rd_out_B[20]
    DIRECTION OUTPUT ;
    USE SIGNAL ;
    SHAPE ABUTMENT ;
    PORT
      LAYER M4 ;
      RECT 93.836 66.432 93.860 66.456 ;
    END
  END rd_out_B[20]
  PIN rd_out_A[21]
    DIRECTION OUTPUT ;
    USE SIGNAL ;
    SHAPE ABUTMENT ;
    PORT
      LAYER M4 ;
      RECT 0.000 67.200 0.024 67.224 ;
    END
  END rd_out_A[21]
  PIN rd_out_B[21]
    DIRECTION OUTPUT ;
    USE SIGNAL ;
    SHAPE ABUTMENT ;
    PORT
      LAYER M4 ;
      RECT 93.836 67.200 93.860 67.224 ;
    END
  END rd_out_B[21]
  PIN rd_out_A[22]
    DIRECTION OUTPUT ;
    USE SIGNAL ;
    SHAPE ABUTMENT ;
    PORT
      LAYER M4 ;
      RECT 0.000 67.968 0.024 67.992 ;
    END
  END rd_out_A[22]
  PIN rd_out_B[22]
    DIRECTION OUTPUT ;
    USE SIGNAL ;
    SHAPE ABUTMENT ;
    PORT
      LAYER M4 ;
      RECT 93.836 67.968 93.860 67.992 ;
    END
  END rd_out_B[22]
  PIN rd_out_A[23]
    DIRECTION OUTPUT ;
    USE SIGNAL ;
    SHAPE ABUTMENT ;
    PORT
      LAYER M4 ;
      RECT 0.000 68.736 0.024 68.760 ;
    END
  END rd_out_A[23]
  PIN rd_out_B[23]
    DIRECTION OUTPUT ;
    USE SIGNAL ;
    SHAPE ABUTMENT ;
    PORT
      LAYER M4 ;
      RECT 93.836 68.736 93.860 68.760 ;
    END
  END rd_out_B[23]
  PIN rd_out_A[24]
    DIRECTION OUTPUT ;
    USE SIGNAL ;
    SHAPE ABUTMENT ;
    PORT
      LAYER M4 ;
      RECT 0.000 69.504 0.024 69.528 ;
    END
  END rd_out_A[24]
  PIN rd_out_B[24]
    DIRECTION OUTPUT ;
    USE SIGNAL ;
    SHAPE ABUTMENT ;
    PORT
      LAYER M4 ;
      RECT 93.836 69.504 93.860 69.528 ;
    END
  END rd_out_B[24]
  PIN rd_out_A[25]
    DIRECTION OUTPUT ;
    USE SIGNAL ;
    SHAPE ABUTMENT ;
    PORT
      LAYER M4 ;
      RECT 0.000 70.272 0.024 70.296 ;
    END
  END rd_out_A[25]
  PIN rd_out_B[25]
    DIRECTION OUTPUT ;
    USE SIGNAL ;
    SHAPE ABUTMENT ;
    PORT
      LAYER M4 ;
      RECT 93.836 70.272 93.860 70.296 ;
    END
  END rd_out_B[25]
  PIN rd_out_A[26]
    DIRECTION OUTPUT ;
    USE SIGNAL ;
    SHAPE ABUTMENT ;
    PORT
      LAYER M4 ;
      RECT 0.000 71.040 0.024 71.064 ;
    END
  END rd_out_A[26]
  PIN rd_out_B[26]
    DIRECTION OUTPUT ;
    USE SIGNAL ;
    SHAPE ABUTMENT ;
    PORT
      LAYER M4 ;
      RECT 93.836 71.040 93.860 71.064 ;
    END
  END rd_out_B[26]
  PIN rd_out_A[27]
    DIRECTION OUTPUT ;
    USE SIGNAL ;
    SHAPE ABUTMENT ;
    PORT
      LAYER M4 ;
      RECT 0.000 71.808 0.024 71.832 ;
    END
  END rd_out_A[27]
  PIN rd_out_B[27]
    DIRECTION OUTPUT ;
    USE SIGNAL ;
    SHAPE ABUTMENT ;
    PORT
      LAYER M4 ;
      RECT 93.836 71.808 93.860 71.832 ;
    END
  END rd_out_B[27]
  PIN rd_out_A[28]
    DIRECTION OUTPUT ;
    USE SIGNAL ;
    SHAPE ABUTMENT ;
    PORT
      LAYER M4 ;
      RECT 0.000 72.576 0.024 72.600 ;
    END
  END rd_out_A[28]
  PIN rd_out_B[28]
    DIRECTION OUTPUT ;
    USE SIGNAL ;
    SHAPE ABUTMENT ;
    PORT
      LAYER M4 ;
      RECT 93.836 72.576 93.860 72.600 ;
    END
  END rd_out_B[28]
  PIN rd_out_A[29]
    DIRECTION OUTPUT ;
    USE SIGNAL ;
    SHAPE ABUTMENT ;
    PORT
      LAYER M4 ;
      RECT 0.000 73.344 0.024 73.368 ;
    END
  END rd_out_A[29]
  PIN rd_out_B[29]
    DIRECTION OUTPUT ;
    USE SIGNAL ;
    SHAPE ABUTMENT ;
    PORT
      LAYER M4 ;
      RECT 93.836 73.344 93.860 73.368 ;
    END
  END rd_out_B[29]
  PIN rd_out_A[30]
    DIRECTION OUTPUT ;
    USE SIGNAL ;
    SHAPE ABUTMENT ;
    PORT
      LAYER M4 ;
      RECT 0.000 74.112 0.024 74.136 ;
    END
  END rd_out_A[30]
  PIN rd_out_B[30]
    DIRECTION OUTPUT ;
    USE SIGNAL ;
    SHAPE ABUTMENT ;
    PORT
      LAYER M4 ;
      RECT 93.836 74.112 93.860 74.136 ;
    END
  END rd_out_B[30]
  PIN rd_out_A[31]
    DIRECTION OUTPUT ;
    USE SIGNAL ;
    SHAPE ABUTMENT ;
    PORT
      LAYER M4 ;
      RECT 0.000 74.880 0.024 74.904 ;
    END
  END rd_out_A[31]
  PIN rd_out_B[31]
    DIRECTION OUTPUT ;
    USE SIGNAL ;
    SHAPE ABUTMENT ;
    PORT
      LAYER M4 ;
      RECT 93.836 74.880 93.860 74.904 ;
    END
  END rd_out_B[31]
  PIN rd_out_A[32]
    DIRECTION OUTPUT ;
    USE SIGNAL ;
    SHAPE ABUTMENT ;
    PORT
      LAYER M4 ;
      RECT 0.000 75.648 0.024 75.672 ;
    END
  END rd_out_A[32]
  PIN rd_out_B[32]
    DIRECTION OUTPUT ;
    USE SIGNAL ;
    SHAPE ABUTMENT ;
    PORT
      LAYER M4 ;
      RECT 93.836 75.648 93.860 75.672 ;
    END
  END rd_out_B[32]
  PIN rd_out_A[33]
    DIRECTION OUTPUT ;
    USE SIGNAL ;
    SHAPE ABUTMENT ;
    PORT
      LAYER M4 ;
      RECT 0.000 76.416 0.024 76.440 ;
    END
  END rd_out_A[33]
  PIN rd_out_B[33]
    DIRECTION OUTPUT ;
    USE SIGNAL ;
    SHAPE ABUTMENT ;
    PORT
      LAYER M4 ;
      RECT 93.836 76.416 93.860 76.440 ;
    END
  END rd_out_B[33]
  PIN rd_out_A[34]
    DIRECTION OUTPUT ;
    USE SIGNAL ;
    SHAPE ABUTMENT ;
    PORT
      LAYER M4 ;
      RECT 0.000 77.184 0.024 77.208 ;
    END
  END rd_out_A[34]
  PIN rd_out_B[34]
    DIRECTION OUTPUT ;
    USE SIGNAL ;
    SHAPE ABUTMENT ;
    PORT
      LAYER M4 ;
      RECT 93.836 77.184 93.860 77.208 ;
    END
  END rd_out_B[34]
  PIN rd_out_A[35]
    DIRECTION OUTPUT ;
    USE SIGNAL ;
    SHAPE ABUTMENT ;
    PORT
      LAYER M4 ;
      RECT 0.000 77.952 0.024 77.976 ;
    END
  END rd_out_A[35]
  PIN rd_out_B[35]
    DIRECTION OUTPUT ;
    USE SIGNAL ;
    SHAPE ABUTMENT ;
    PORT
      LAYER M4 ;
      RECT 93.836 77.952 93.860 77.976 ;
    END
  END rd_out_B[35]
  PIN rd_out_A[36]
    DIRECTION OUTPUT ;
    USE SIGNAL ;
    SHAPE ABUTMENT ;
    PORT
      LAYER M4 ;
      RECT 0.000 78.720 0.024 78.744 ;
    END
  END rd_out_A[36]
  PIN rd_out_B[36]
    DIRECTION OUTPUT ;
    USE SIGNAL ;
    SHAPE ABUTMENT ;
    PORT
      LAYER M4 ;
      RECT 93.836 78.720 93.860 78.744 ;
    END
  END rd_out_B[36]
  PIN rd_out_A[37]
    DIRECTION OUTPUT ;
    USE SIGNAL ;
    SHAPE ABUTMENT ;
    PORT
      LAYER M4 ;
      RECT 0.000 79.488 0.024 79.512 ;
    END
  END rd_out_A[37]
  PIN rd_out_B[37]
    DIRECTION OUTPUT ;
    USE SIGNAL ;
    SHAPE ABUTMENT ;
    PORT
      LAYER M4 ;
      RECT 93.836 79.488 93.860 79.512 ;
    END
  END rd_out_B[37]
  PIN rd_out_A[38]
    DIRECTION OUTPUT ;
    USE SIGNAL ;
    SHAPE ABUTMENT ;
    PORT
      LAYER M4 ;
      RECT 0.000 80.256 0.024 80.280 ;
    END
  END rd_out_A[38]
  PIN rd_out_B[38]
    DIRECTION OUTPUT ;
    USE SIGNAL ;
    SHAPE ABUTMENT ;
    PORT
      LAYER M4 ;
      RECT 93.836 80.256 93.860 80.280 ;
    END
  END rd_out_B[38]
  PIN rd_out_A[39]
    DIRECTION OUTPUT ;
    USE SIGNAL ;
    SHAPE ABUTMENT ;
    PORT
      LAYER M4 ;
      RECT 0.000 81.024 0.024 81.048 ;
    END
  END rd_out_A[39]
  PIN rd_out_B[39]
    DIRECTION OUTPUT ;
    USE SIGNAL ;
    SHAPE ABUTMENT ;
    PORT
      LAYER M4 ;
      RECT 93.836 81.024 93.860 81.048 ;
    END
  END rd_out_B[39]
  PIN rd_out_A[40]
    DIRECTION OUTPUT ;
    USE SIGNAL ;
    SHAPE ABUTMENT ;
    PORT
      LAYER M4 ;
      RECT 0.000 81.792 0.024 81.816 ;
    END
  END rd_out_A[40]
  PIN rd_out_B[40]
    DIRECTION OUTPUT ;
    USE SIGNAL ;
    SHAPE ABUTMENT ;
    PORT
      LAYER M4 ;
      RECT 93.836 81.792 93.860 81.816 ;
    END
  END rd_out_B[40]
  PIN rd_out_A[41]
    DIRECTION OUTPUT ;
    USE SIGNAL ;
    SHAPE ABUTMENT ;
    PORT
      LAYER M4 ;
      RECT 0.000 82.560 0.024 82.584 ;
    END
  END rd_out_A[41]
  PIN rd_out_B[41]
    DIRECTION OUTPUT ;
    USE SIGNAL ;
    SHAPE ABUTMENT ;
    PORT
      LAYER M4 ;
      RECT 93.836 82.560 93.860 82.584 ;
    END
  END rd_out_B[41]
  PIN rd_out_A[42]
    DIRECTION OUTPUT ;
    USE SIGNAL ;
    SHAPE ABUTMENT ;
    PORT
      LAYER M4 ;
      RECT 0.000 83.328 0.024 83.352 ;
    END
  END rd_out_A[42]
  PIN rd_out_B[42]
    DIRECTION OUTPUT ;
    USE SIGNAL ;
    SHAPE ABUTMENT ;
    PORT
      LAYER M4 ;
      RECT 93.836 83.328 93.860 83.352 ;
    END
  END rd_out_B[42]
  PIN rd_out_A[43]
    DIRECTION OUTPUT ;
    USE SIGNAL ;
    SHAPE ABUTMENT ;
    PORT
      LAYER M4 ;
      RECT 0.000 84.096 0.024 84.120 ;
    END
  END rd_out_A[43]
  PIN rd_out_B[43]
    DIRECTION OUTPUT ;
    USE SIGNAL ;
    SHAPE ABUTMENT ;
    PORT
      LAYER M4 ;
      RECT 93.836 84.096 93.860 84.120 ;
    END
  END rd_out_B[43]
  PIN rd_out_A[44]
    DIRECTION OUTPUT ;
    USE SIGNAL ;
    SHAPE ABUTMENT ;
    PORT
      LAYER M4 ;
      RECT 0.000 84.864 0.024 84.888 ;
    END
  END rd_out_A[44]
  PIN rd_out_B[44]
    DIRECTION OUTPUT ;
    USE SIGNAL ;
    SHAPE ABUTMENT ;
    PORT
      LAYER M4 ;
      RECT 93.836 84.864 93.860 84.888 ;
    END
  END rd_out_B[44]
  PIN rd_out_A[45]
    DIRECTION OUTPUT ;
    USE SIGNAL ;
    SHAPE ABUTMENT ;
    PORT
      LAYER M4 ;
      RECT 0.000 85.632 0.024 85.656 ;
    END
  END rd_out_A[45]
  PIN rd_out_B[45]
    DIRECTION OUTPUT ;
    USE SIGNAL ;
    SHAPE ABUTMENT ;
    PORT
      LAYER M4 ;
      RECT 93.836 85.632 93.860 85.656 ;
    END
  END rd_out_B[45]
  PIN rd_out_A[46]
    DIRECTION OUTPUT ;
    USE SIGNAL ;
    SHAPE ABUTMENT ;
    PORT
      LAYER M4 ;
      RECT 0.000 86.400 0.024 86.424 ;
    END
  END rd_out_A[46]
  PIN rd_out_B[46]
    DIRECTION OUTPUT ;
    USE SIGNAL ;
    SHAPE ABUTMENT ;
    PORT
      LAYER M4 ;
      RECT 93.836 86.400 93.860 86.424 ;
    END
  END rd_out_B[46]
  PIN rd_out_A[47]
    DIRECTION OUTPUT ;
    USE SIGNAL ;
    SHAPE ABUTMENT ;
    PORT
      LAYER M4 ;
      RECT 0.000 87.168 0.024 87.192 ;
    END
  END rd_out_A[47]
  PIN rd_out_B[47]
    DIRECTION OUTPUT ;
    USE SIGNAL ;
    SHAPE ABUTMENT ;
    PORT
      LAYER M4 ;
      RECT 93.836 87.168 93.860 87.192 ;
    END
  END rd_out_B[47]
  PIN rd_out_A[48]
    DIRECTION OUTPUT ;
    USE SIGNAL ;
    SHAPE ABUTMENT ;
    PORT
      LAYER M4 ;
      RECT 0.000 87.936 0.024 87.960 ;
    END
  END rd_out_A[48]
  PIN rd_out_B[48]
    DIRECTION OUTPUT ;
    USE SIGNAL ;
    SHAPE ABUTMENT ;
    PORT
      LAYER M4 ;
      RECT 93.836 87.936 93.860 87.960 ;
    END
  END rd_out_B[48]
  PIN rd_out_A[49]
    DIRECTION OUTPUT ;
    USE SIGNAL ;
    SHAPE ABUTMENT ;
    PORT
      LAYER M4 ;
      RECT 0.000 88.704 0.024 88.728 ;
    END
  END rd_out_A[49]
  PIN rd_out_B[49]
    DIRECTION OUTPUT ;
    USE SIGNAL ;
    SHAPE ABUTMENT ;
    PORT
      LAYER M4 ;
      RECT 93.836 88.704 93.860 88.728 ;
    END
  END rd_out_B[49]
  PIN rd_out_A[50]
    DIRECTION OUTPUT ;
    USE SIGNAL ;
    SHAPE ABUTMENT ;
    PORT
      LAYER M4 ;
      RECT 0.000 89.472 0.024 89.496 ;
    END
  END rd_out_A[50]
  PIN rd_out_B[50]
    DIRECTION OUTPUT ;
    USE SIGNAL ;
    SHAPE ABUTMENT ;
    PORT
      LAYER M4 ;
      RECT 93.836 89.472 93.860 89.496 ;
    END
  END rd_out_B[50]
  PIN rd_out_A[51]
    DIRECTION OUTPUT ;
    USE SIGNAL ;
    SHAPE ABUTMENT ;
    PORT
      LAYER M4 ;
      RECT 0.000 90.240 0.024 90.264 ;
    END
  END rd_out_A[51]
  PIN rd_out_B[51]
    DIRECTION OUTPUT ;
    USE SIGNAL ;
    SHAPE ABUTMENT ;
    PORT
      LAYER M4 ;
      RECT 93.836 90.240 93.860 90.264 ;
    END
  END rd_out_B[51]
  PIN rd_out_A[52]
    DIRECTION OUTPUT ;
    USE SIGNAL ;
    SHAPE ABUTMENT ;
    PORT
      LAYER M4 ;
      RECT 0.000 91.008 0.024 91.032 ;
    END
  END rd_out_A[52]
  PIN rd_out_B[52]
    DIRECTION OUTPUT ;
    USE SIGNAL ;
    SHAPE ABUTMENT ;
    PORT
      LAYER M4 ;
      RECT 93.836 91.008 93.860 91.032 ;
    END
  END rd_out_B[52]
  PIN rd_out_A[53]
    DIRECTION OUTPUT ;
    USE SIGNAL ;
    SHAPE ABUTMENT ;
    PORT
      LAYER M4 ;
      RECT 0.000 91.776 0.024 91.800 ;
    END
  END rd_out_A[53]
  PIN rd_out_B[53]
    DIRECTION OUTPUT ;
    USE SIGNAL ;
    SHAPE ABUTMENT ;
    PORT
      LAYER M4 ;
      RECT 93.836 91.776 93.860 91.800 ;
    END
  END rd_out_B[53]
  PIN rd_out_A[54]
    DIRECTION OUTPUT ;
    USE SIGNAL ;
    SHAPE ABUTMENT ;
    PORT
      LAYER M4 ;
      RECT 0.000 92.544 0.024 92.568 ;
    END
  END rd_out_A[54]
  PIN rd_out_B[54]
    DIRECTION OUTPUT ;
    USE SIGNAL ;
    SHAPE ABUTMENT ;
    PORT
      LAYER M4 ;
      RECT 93.836 92.544 93.860 92.568 ;
    END
  END rd_out_B[54]
  PIN rd_out_A[55]
    DIRECTION OUTPUT ;
    USE SIGNAL ;
    SHAPE ABUTMENT ;
    PORT
      LAYER M4 ;
      RECT 0.000 93.312 0.024 93.336 ;
    END
  END rd_out_A[55]
  PIN rd_out_B[55]
    DIRECTION OUTPUT ;
    USE SIGNAL ;
    SHAPE ABUTMENT ;
    PORT
      LAYER M4 ;
      RECT 93.836 93.312 93.860 93.336 ;
    END
  END rd_out_B[55]
  PIN rd_out_A[56]
    DIRECTION OUTPUT ;
    USE SIGNAL ;
    SHAPE ABUTMENT ;
    PORT
      LAYER M4 ;
      RECT 0.000 94.080 0.024 94.104 ;
    END
  END rd_out_A[56]
  PIN rd_out_B[56]
    DIRECTION OUTPUT ;
    USE SIGNAL ;
    SHAPE ABUTMENT ;
    PORT
      LAYER M4 ;
      RECT 93.836 94.080 93.860 94.104 ;
    END
  END rd_out_B[56]
  PIN rd_out_A[57]
    DIRECTION OUTPUT ;
    USE SIGNAL ;
    SHAPE ABUTMENT ;
    PORT
      LAYER M4 ;
      RECT 0.000 94.848 0.024 94.872 ;
    END
  END rd_out_A[57]
  PIN rd_out_B[57]
    DIRECTION OUTPUT ;
    USE SIGNAL ;
    SHAPE ABUTMENT ;
    PORT
      LAYER M4 ;
      RECT 93.836 94.848 93.860 94.872 ;
    END
  END rd_out_B[57]
  PIN rd_out_A[58]
    DIRECTION OUTPUT ;
    USE SIGNAL ;
    SHAPE ABUTMENT ;
    PORT
      LAYER M4 ;
      RECT 0.000 95.616 0.024 95.640 ;
    END
  END rd_out_A[58]
  PIN rd_out_B[58]
    DIRECTION OUTPUT ;
    USE SIGNAL ;
    SHAPE ABUTMENT ;
    PORT
      LAYER M4 ;
      RECT 93.836 95.616 93.860 95.640 ;
    END
  END rd_out_B[58]
  PIN rd_out_A[59]
    DIRECTION OUTPUT ;
    USE SIGNAL ;
    SHAPE ABUTMENT ;
    PORT
      LAYER M4 ;
      RECT 0.000 96.384 0.024 96.408 ;
    END
  END rd_out_A[59]
  PIN rd_out_B[59]
    DIRECTION OUTPUT ;
    USE SIGNAL ;
    SHAPE ABUTMENT ;
    PORT
      LAYER M4 ;
      RECT 93.836 96.384 93.860 96.408 ;
    END
  END rd_out_B[59]
  PIN rd_out_A[60]
    DIRECTION OUTPUT ;
    USE SIGNAL ;
    SHAPE ABUTMENT ;
    PORT
      LAYER M4 ;
      RECT 0.000 97.152 0.024 97.176 ;
    END
  END rd_out_A[60]
  PIN rd_out_B[60]
    DIRECTION OUTPUT ;
    USE SIGNAL ;
    SHAPE ABUTMENT ;
    PORT
      LAYER M4 ;
      RECT 93.836 97.152 93.860 97.176 ;
    END
  END rd_out_B[60]
  PIN rd_out_A[61]
    DIRECTION OUTPUT ;
    USE SIGNAL ;
    SHAPE ABUTMENT ;
    PORT
      LAYER M4 ;
      RECT 0.000 97.920 0.024 97.944 ;
    END
  END rd_out_A[61]
  PIN rd_out_B[61]
    DIRECTION OUTPUT ;
    USE SIGNAL ;
    SHAPE ABUTMENT ;
    PORT
      LAYER M4 ;
      RECT 93.836 97.920 93.860 97.944 ;
    END
  END rd_out_B[61]
  PIN rd_out_A[62]
    DIRECTION OUTPUT ;
    USE SIGNAL ;
    SHAPE ABUTMENT ;
    PORT
      LAYER M4 ;
      RECT 0.000 98.688 0.024 98.712 ;
    END
  END rd_out_A[62]
  PIN rd_out_B[62]
    DIRECTION OUTPUT ;
    USE SIGNAL ;
    SHAPE ABUTMENT ;
    PORT
      LAYER M4 ;
      RECT 93.836 98.688 93.860 98.712 ;
    END
  END rd_out_B[62]
  PIN rd_out_A[63]
    DIRECTION OUTPUT ;
    USE SIGNAL ;
    SHAPE ABUTMENT ;
    PORT
      LAYER M4 ;
      RECT 0.000 99.456 0.024 99.480 ;
    END
  END rd_out_A[63]
  PIN rd_out_B[63]
    DIRECTION OUTPUT ;
    USE SIGNAL ;
    SHAPE ABUTMENT ;
    PORT
      LAYER M4 ;
      RECT 93.836 99.456 93.860 99.480 ;
    END
  END rd_out_B[63]
  PIN wd_in_A[0]
    DIRECTION INPUT ;
    USE SIGNAL ;
    SHAPE ABUTMENT ;
    PORT
      LAYER M4 ;
      RECT 0.000 102.096 0.024 102.120 ;
    END
  END wd_in_A[0]
  PIN wd_in_B[0]
    DIRECTION INPUT ;
    USE SIGNAL ;
    SHAPE ABUTMENT ;
    PORT
      LAYER M4 ;
      RECT 93.836 102.096 93.860 102.120 ;
    END
  END wd_in_B[0]
  PIN wd_in_A[1]
    DIRECTION INPUT ;
    USE SIGNAL ;
    SHAPE ABUTMENT ;
    PORT
      LAYER M4 ;
      RECT 0.000 102.864 0.024 102.888 ;
    END
  END wd_in_A[1]
  PIN wd_in_B[1]
    DIRECTION INPUT ;
    USE SIGNAL ;
    SHAPE ABUTMENT ;
    PORT
      LAYER M4 ;
      RECT 93.836 102.864 93.860 102.888 ;
    END
  END wd_in_B[1]
  PIN wd_in_A[2]
    DIRECTION INPUT ;
    USE SIGNAL ;
    SHAPE ABUTMENT ;
    PORT
      LAYER M4 ;
      RECT 0.000 103.632 0.024 103.656 ;
    END
  END wd_in_A[2]
  PIN wd_in_B[2]
    DIRECTION INPUT ;
    USE SIGNAL ;
    SHAPE ABUTMENT ;
    PORT
      LAYER M4 ;
      RECT 93.836 103.632 93.860 103.656 ;
    END
  END wd_in_B[2]
  PIN wd_in_A[3]
    DIRECTION INPUT ;
    USE SIGNAL ;
    SHAPE ABUTMENT ;
    PORT
      LAYER M4 ;
      RECT 0.000 104.400 0.024 104.424 ;
    END
  END wd_in_A[3]
  PIN wd_in_B[3]
    DIRECTION INPUT ;
    USE SIGNAL ;
    SHAPE ABUTMENT ;
    PORT
      LAYER M4 ;
      RECT 93.836 104.400 93.860 104.424 ;
    END
  END wd_in_B[3]
  PIN wd_in_A[4]
    DIRECTION INPUT ;
    USE SIGNAL ;
    SHAPE ABUTMENT ;
    PORT
      LAYER M4 ;
      RECT 0.000 105.168 0.024 105.192 ;
    END
  END wd_in_A[4]
  PIN wd_in_B[4]
    DIRECTION INPUT ;
    USE SIGNAL ;
    SHAPE ABUTMENT ;
    PORT
      LAYER M4 ;
      RECT 93.836 105.168 93.860 105.192 ;
    END
  END wd_in_B[4]
  PIN wd_in_A[5]
    DIRECTION INPUT ;
    USE SIGNAL ;
    SHAPE ABUTMENT ;
    PORT
      LAYER M4 ;
      RECT 0.000 105.936 0.024 105.960 ;
    END
  END wd_in_A[5]
  PIN wd_in_B[5]
    DIRECTION INPUT ;
    USE SIGNAL ;
    SHAPE ABUTMENT ;
    PORT
      LAYER M4 ;
      RECT 93.836 105.936 93.860 105.960 ;
    END
  END wd_in_B[5]
  PIN wd_in_A[6]
    DIRECTION INPUT ;
    USE SIGNAL ;
    SHAPE ABUTMENT ;
    PORT
      LAYER M4 ;
      RECT 0.000 106.704 0.024 106.728 ;
    END
  END wd_in_A[6]
  PIN wd_in_B[6]
    DIRECTION INPUT ;
    USE SIGNAL ;
    SHAPE ABUTMENT ;
    PORT
      LAYER M4 ;
      RECT 93.836 106.704 93.860 106.728 ;
    END
  END wd_in_B[6]
  PIN wd_in_A[7]
    DIRECTION INPUT ;
    USE SIGNAL ;
    SHAPE ABUTMENT ;
    PORT
      LAYER M4 ;
      RECT 0.000 107.472 0.024 107.496 ;
    END
  END wd_in_A[7]
  PIN wd_in_B[7]
    DIRECTION INPUT ;
    USE SIGNAL ;
    SHAPE ABUTMENT ;
    PORT
      LAYER M4 ;
      RECT 93.836 107.472 93.860 107.496 ;
    END
  END wd_in_B[7]
  PIN wd_in_A[8]
    DIRECTION INPUT ;
    USE SIGNAL ;
    SHAPE ABUTMENT ;
    PORT
      LAYER M4 ;
      RECT 0.000 108.240 0.024 108.264 ;
    END
  END wd_in_A[8]
  PIN wd_in_B[8]
    DIRECTION INPUT ;
    USE SIGNAL ;
    SHAPE ABUTMENT ;
    PORT
      LAYER M4 ;
      RECT 93.836 108.240 93.860 108.264 ;
    END
  END wd_in_B[8]
  PIN wd_in_A[9]
    DIRECTION INPUT ;
    USE SIGNAL ;
    SHAPE ABUTMENT ;
    PORT
      LAYER M4 ;
      RECT 0.000 109.008 0.024 109.032 ;
    END
  END wd_in_A[9]
  PIN wd_in_B[9]
    DIRECTION INPUT ;
    USE SIGNAL ;
    SHAPE ABUTMENT ;
    PORT
      LAYER M4 ;
      RECT 93.836 109.008 93.860 109.032 ;
    END
  END wd_in_B[9]
  PIN wd_in_A[10]
    DIRECTION INPUT ;
    USE SIGNAL ;
    SHAPE ABUTMENT ;
    PORT
      LAYER M4 ;
      RECT 0.000 109.776 0.024 109.800 ;
    END
  END wd_in_A[10]
  PIN wd_in_B[10]
    DIRECTION INPUT ;
    USE SIGNAL ;
    SHAPE ABUTMENT ;
    PORT
      LAYER M4 ;
      RECT 93.836 109.776 93.860 109.800 ;
    END
  END wd_in_B[10]
  PIN wd_in_A[11]
    DIRECTION INPUT ;
    USE SIGNAL ;
    SHAPE ABUTMENT ;
    PORT
      LAYER M4 ;
      RECT 0.000 110.544 0.024 110.568 ;
    END
  END wd_in_A[11]
  PIN wd_in_B[11]
    DIRECTION INPUT ;
    USE SIGNAL ;
    SHAPE ABUTMENT ;
    PORT
      LAYER M4 ;
      RECT 93.836 110.544 93.860 110.568 ;
    END
  END wd_in_B[11]
  PIN wd_in_A[12]
    DIRECTION INPUT ;
    USE SIGNAL ;
    SHAPE ABUTMENT ;
    PORT
      LAYER M4 ;
      RECT 0.000 111.312 0.024 111.336 ;
    END
  END wd_in_A[12]
  PIN wd_in_B[12]
    DIRECTION INPUT ;
    USE SIGNAL ;
    SHAPE ABUTMENT ;
    PORT
      LAYER M4 ;
      RECT 93.836 111.312 93.860 111.336 ;
    END
  END wd_in_B[12]
  PIN wd_in_A[13]
    DIRECTION INPUT ;
    USE SIGNAL ;
    SHAPE ABUTMENT ;
    PORT
      LAYER M4 ;
      RECT 0.000 112.080 0.024 112.104 ;
    END
  END wd_in_A[13]
  PIN wd_in_B[13]
    DIRECTION INPUT ;
    USE SIGNAL ;
    SHAPE ABUTMENT ;
    PORT
      LAYER M4 ;
      RECT 93.836 112.080 93.860 112.104 ;
    END
  END wd_in_B[13]
  PIN wd_in_A[14]
    DIRECTION INPUT ;
    USE SIGNAL ;
    SHAPE ABUTMENT ;
    PORT
      LAYER M4 ;
      RECT 0.000 112.848 0.024 112.872 ;
    END
  END wd_in_A[14]
  PIN wd_in_B[14]
    DIRECTION INPUT ;
    USE SIGNAL ;
    SHAPE ABUTMENT ;
    PORT
      LAYER M4 ;
      RECT 93.836 112.848 93.860 112.872 ;
    END
  END wd_in_B[14]
  PIN wd_in_A[15]
    DIRECTION INPUT ;
    USE SIGNAL ;
    SHAPE ABUTMENT ;
    PORT
      LAYER M4 ;
      RECT 0.000 113.616 0.024 113.640 ;
    END
  END wd_in_A[15]
  PIN wd_in_B[15]
    DIRECTION INPUT ;
    USE SIGNAL ;
    SHAPE ABUTMENT ;
    PORT
      LAYER M4 ;
      RECT 93.836 113.616 93.860 113.640 ;
    END
  END wd_in_B[15]
  PIN wd_in_A[16]
    DIRECTION INPUT ;
    USE SIGNAL ;
    SHAPE ABUTMENT ;
    PORT
      LAYER M4 ;
      RECT 0.000 114.384 0.024 114.408 ;
    END
  END wd_in_A[16]
  PIN wd_in_B[16]
    DIRECTION INPUT ;
    USE SIGNAL ;
    SHAPE ABUTMENT ;
    PORT
      LAYER M4 ;
      RECT 93.836 114.384 93.860 114.408 ;
    END
  END wd_in_B[16]
  PIN wd_in_A[17]
    DIRECTION INPUT ;
    USE SIGNAL ;
    SHAPE ABUTMENT ;
    PORT
      LAYER M4 ;
      RECT 0.000 115.152 0.024 115.176 ;
    END
  END wd_in_A[17]
  PIN wd_in_B[17]
    DIRECTION INPUT ;
    USE SIGNAL ;
    SHAPE ABUTMENT ;
    PORT
      LAYER M4 ;
      RECT 93.836 115.152 93.860 115.176 ;
    END
  END wd_in_B[17]
  PIN wd_in_A[18]
    DIRECTION INPUT ;
    USE SIGNAL ;
    SHAPE ABUTMENT ;
    PORT
      LAYER M4 ;
      RECT 0.000 115.920 0.024 115.944 ;
    END
  END wd_in_A[18]
  PIN wd_in_B[18]
    DIRECTION INPUT ;
    USE SIGNAL ;
    SHAPE ABUTMENT ;
    PORT
      LAYER M4 ;
      RECT 93.836 115.920 93.860 115.944 ;
    END
  END wd_in_B[18]
  PIN wd_in_A[19]
    DIRECTION INPUT ;
    USE SIGNAL ;
    SHAPE ABUTMENT ;
    PORT
      LAYER M4 ;
      RECT 0.000 116.688 0.024 116.712 ;
    END
  END wd_in_A[19]
  PIN wd_in_B[19]
    DIRECTION INPUT ;
    USE SIGNAL ;
    SHAPE ABUTMENT ;
    PORT
      LAYER M4 ;
      RECT 93.836 116.688 93.860 116.712 ;
    END
  END wd_in_B[19]
  PIN wd_in_A[20]
    DIRECTION INPUT ;
    USE SIGNAL ;
    SHAPE ABUTMENT ;
    PORT
      LAYER M4 ;
      RECT 0.000 117.456 0.024 117.480 ;
    END
  END wd_in_A[20]
  PIN wd_in_B[20]
    DIRECTION INPUT ;
    USE SIGNAL ;
    SHAPE ABUTMENT ;
    PORT
      LAYER M4 ;
      RECT 93.836 117.456 93.860 117.480 ;
    END
  END wd_in_B[20]
  PIN wd_in_A[21]
    DIRECTION INPUT ;
    USE SIGNAL ;
    SHAPE ABUTMENT ;
    PORT
      LAYER M4 ;
      RECT 0.000 118.224 0.024 118.248 ;
    END
  END wd_in_A[21]
  PIN wd_in_B[21]
    DIRECTION INPUT ;
    USE SIGNAL ;
    SHAPE ABUTMENT ;
    PORT
      LAYER M4 ;
      RECT 93.836 118.224 93.860 118.248 ;
    END
  END wd_in_B[21]
  PIN wd_in_A[22]
    DIRECTION INPUT ;
    USE SIGNAL ;
    SHAPE ABUTMENT ;
    PORT
      LAYER M4 ;
      RECT 0.000 118.992 0.024 119.016 ;
    END
  END wd_in_A[22]
  PIN wd_in_B[22]
    DIRECTION INPUT ;
    USE SIGNAL ;
    SHAPE ABUTMENT ;
    PORT
      LAYER M4 ;
      RECT 93.836 118.992 93.860 119.016 ;
    END
  END wd_in_B[22]
  PIN wd_in_A[23]
    DIRECTION INPUT ;
    USE SIGNAL ;
    SHAPE ABUTMENT ;
    PORT
      LAYER M4 ;
      RECT 0.000 119.760 0.024 119.784 ;
    END
  END wd_in_A[23]
  PIN wd_in_B[23]
    DIRECTION INPUT ;
    USE SIGNAL ;
    SHAPE ABUTMENT ;
    PORT
      LAYER M4 ;
      RECT 93.836 119.760 93.860 119.784 ;
    END
  END wd_in_B[23]
  PIN wd_in_A[24]
    DIRECTION INPUT ;
    USE SIGNAL ;
    SHAPE ABUTMENT ;
    PORT
      LAYER M4 ;
      RECT 0.000 120.528 0.024 120.552 ;
    END
  END wd_in_A[24]
  PIN wd_in_B[24]
    DIRECTION INPUT ;
    USE SIGNAL ;
    SHAPE ABUTMENT ;
    PORT
      LAYER M4 ;
      RECT 93.836 120.528 93.860 120.552 ;
    END
  END wd_in_B[24]
  PIN wd_in_A[25]
    DIRECTION INPUT ;
    USE SIGNAL ;
    SHAPE ABUTMENT ;
    PORT
      LAYER M4 ;
      RECT 0.000 121.296 0.024 121.320 ;
    END
  END wd_in_A[25]
  PIN wd_in_B[25]
    DIRECTION INPUT ;
    USE SIGNAL ;
    SHAPE ABUTMENT ;
    PORT
      LAYER M4 ;
      RECT 93.836 121.296 93.860 121.320 ;
    END
  END wd_in_B[25]
  PIN wd_in_A[26]
    DIRECTION INPUT ;
    USE SIGNAL ;
    SHAPE ABUTMENT ;
    PORT
      LAYER M4 ;
      RECT 0.000 122.064 0.024 122.088 ;
    END
  END wd_in_A[26]
  PIN wd_in_B[26]
    DIRECTION INPUT ;
    USE SIGNAL ;
    SHAPE ABUTMENT ;
    PORT
      LAYER M4 ;
      RECT 93.836 122.064 93.860 122.088 ;
    END
  END wd_in_B[26]
  PIN wd_in_A[27]
    DIRECTION INPUT ;
    USE SIGNAL ;
    SHAPE ABUTMENT ;
    PORT
      LAYER M4 ;
      RECT 0.000 122.832 0.024 122.856 ;
    END
  END wd_in_A[27]
  PIN wd_in_B[27]
    DIRECTION INPUT ;
    USE SIGNAL ;
    SHAPE ABUTMENT ;
    PORT
      LAYER M4 ;
      RECT 93.836 122.832 93.860 122.856 ;
    END
  END wd_in_B[27]
  PIN wd_in_A[28]
    DIRECTION INPUT ;
    USE SIGNAL ;
    SHAPE ABUTMENT ;
    PORT
      LAYER M4 ;
      RECT 0.000 123.600 0.024 123.624 ;
    END
  END wd_in_A[28]
  PIN wd_in_B[28]
    DIRECTION INPUT ;
    USE SIGNAL ;
    SHAPE ABUTMENT ;
    PORT
      LAYER M4 ;
      RECT 93.836 123.600 93.860 123.624 ;
    END
  END wd_in_B[28]
  PIN wd_in_A[29]
    DIRECTION INPUT ;
    USE SIGNAL ;
    SHAPE ABUTMENT ;
    PORT
      LAYER M4 ;
      RECT 0.000 124.368 0.024 124.392 ;
    END
  END wd_in_A[29]
  PIN wd_in_B[29]
    DIRECTION INPUT ;
    USE SIGNAL ;
    SHAPE ABUTMENT ;
    PORT
      LAYER M4 ;
      RECT 93.836 124.368 93.860 124.392 ;
    END
  END wd_in_B[29]
  PIN wd_in_A[30]
    DIRECTION INPUT ;
    USE SIGNAL ;
    SHAPE ABUTMENT ;
    PORT
      LAYER M4 ;
      RECT 0.000 125.136 0.024 125.160 ;
    END
  END wd_in_A[30]
  PIN wd_in_B[30]
    DIRECTION INPUT ;
    USE SIGNAL ;
    SHAPE ABUTMENT ;
    PORT
      LAYER M4 ;
      RECT 93.836 125.136 93.860 125.160 ;
    END
  END wd_in_B[30]
  PIN wd_in_A[31]
    DIRECTION INPUT ;
    USE SIGNAL ;
    SHAPE ABUTMENT ;
    PORT
      LAYER M4 ;
      RECT 0.000 125.904 0.024 125.928 ;
    END
  END wd_in_A[31]
  PIN wd_in_B[31]
    DIRECTION INPUT ;
    USE SIGNAL ;
    SHAPE ABUTMENT ;
    PORT
      LAYER M4 ;
      RECT 93.836 125.904 93.860 125.928 ;
    END
  END wd_in_B[31]
  PIN wd_in_A[32]
    DIRECTION INPUT ;
    USE SIGNAL ;
    SHAPE ABUTMENT ;
    PORT
      LAYER M4 ;
      RECT 0.000 126.672 0.024 126.696 ;
    END
  END wd_in_A[32]
  PIN wd_in_B[32]
    DIRECTION INPUT ;
    USE SIGNAL ;
    SHAPE ABUTMENT ;
    PORT
      LAYER M4 ;
      RECT 93.836 126.672 93.860 126.696 ;
    END
  END wd_in_B[32]
  PIN wd_in_A[33]
    DIRECTION INPUT ;
    USE SIGNAL ;
    SHAPE ABUTMENT ;
    PORT
      LAYER M4 ;
      RECT 0.000 127.440 0.024 127.464 ;
    END
  END wd_in_A[33]
  PIN wd_in_B[33]
    DIRECTION INPUT ;
    USE SIGNAL ;
    SHAPE ABUTMENT ;
    PORT
      LAYER M4 ;
      RECT 93.836 127.440 93.860 127.464 ;
    END
  END wd_in_B[33]
  PIN wd_in_A[34]
    DIRECTION INPUT ;
    USE SIGNAL ;
    SHAPE ABUTMENT ;
    PORT
      LAYER M4 ;
      RECT 0.000 128.208 0.024 128.232 ;
    END
  END wd_in_A[34]
  PIN wd_in_B[34]
    DIRECTION INPUT ;
    USE SIGNAL ;
    SHAPE ABUTMENT ;
    PORT
      LAYER M4 ;
      RECT 93.836 128.208 93.860 128.232 ;
    END
  END wd_in_B[34]
  PIN wd_in_A[35]
    DIRECTION INPUT ;
    USE SIGNAL ;
    SHAPE ABUTMENT ;
    PORT
      LAYER M4 ;
      RECT 0.000 128.976 0.024 129.000 ;
    END
  END wd_in_A[35]
  PIN wd_in_B[35]
    DIRECTION INPUT ;
    USE SIGNAL ;
    SHAPE ABUTMENT ;
    PORT
      LAYER M4 ;
      RECT 93.836 128.976 93.860 129.000 ;
    END
  END wd_in_B[35]
  PIN wd_in_A[36]
    DIRECTION INPUT ;
    USE SIGNAL ;
    SHAPE ABUTMENT ;
    PORT
      LAYER M4 ;
      RECT 0.000 129.744 0.024 129.768 ;
    END
  END wd_in_A[36]
  PIN wd_in_B[36]
    DIRECTION INPUT ;
    USE SIGNAL ;
    SHAPE ABUTMENT ;
    PORT
      LAYER M4 ;
      RECT 93.836 129.744 93.860 129.768 ;
    END
  END wd_in_B[36]
  PIN wd_in_A[37]
    DIRECTION INPUT ;
    USE SIGNAL ;
    SHAPE ABUTMENT ;
    PORT
      LAYER M4 ;
      RECT 0.000 130.512 0.024 130.536 ;
    END
  END wd_in_A[37]
  PIN wd_in_B[37]
    DIRECTION INPUT ;
    USE SIGNAL ;
    SHAPE ABUTMENT ;
    PORT
      LAYER M4 ;
      RECT 93.836 130.512 93.860 130.536 ;
    END
  END wd_in_B[37]
  PIN wd_in_A[38]
    DIRECTION INPUT ;
    USE SIGNAL ;
    SHAPE ABUTMENT ;
    PORT
      LAYER M4 ;
      RECT 0.000 131.280 0.024 131.304 ;
    END
  END wd_in_A[38]
  PIN wd_in_B[38]
    DIRECTION INPUT ;
    USE SIGNAL ;
    SHAPE ABUTMENT ;
    PORT
      LAYER M4 ;
      RECT 93.836 131.280 93.860 131.304 ;
    END
  END wd_in_B[38]
  PIN wd_in_A[39]
    DIRECTION INPUT ;
    USE SIGNAL ;
    SHAPE ABUTMENT ;
    PORT
      LAYER M4 ;
      RECT 0.000 132.048 0.024 132.072 ;
    END
  END wd_in_A[39]
  PIN wd_in_B[39]
    DIRECTION INPUT ;
    USE SIGNAL ;
    SHAPE ABUTMENT ;
    PORT
      LAYER M4 ;
      RECT 93.836 132.048 93.860 132.072 ;
    END
  END wd_in_B[39]
  PIN wd_in_A[40]
    DIRECTION INPUT ;
    USE SIGNAL ;
    SHAPE ABUTMENT ;
    PORT
      LAYER M4 ;
      RECT 0.000 132.816 0.024 132.840 ;
    END
  END wd_in_A[40]
  PIN wd_in_B[40]
    DIRECTION INPUT ;
    USE SIGNAL ;
    SHAPE ABUTMENT ;
    PORT
      LAYER M4 ;
      RECT 93.836 132.816 93.860 132.840 ;
    END
  END wd_in_B[40]
  PIN wd_in_A[41]
    DIRECTION INPUT ;
    USE SIGNAL ;
    SHAPE ABUTMENT ;
    PORT
      LAYER M4 ;
      RECT 0.000 133.584 0.024 133.608 ;
    END
  END wd_in_A[41]
  PIN wd_in_B[41]
    DIRECTION INPUT ;
    USE SIGNAL ;
    SHAPE ABUTMENT ;
    PORT
      LAYER M4 ;
      RECT 93.836 133.584 93.860 133.608 ;
    END
  END wd_in_B[41]
  PIN wd_in_A[42]
    DIRECTION INPUT ;
    USE SIGNAL ;
    SHAPE ABUTMENT ;
    PORT
      LAYER M4 ;
      RECT 0.000 134.352 0.024 134.376 ;
    END
  END wd_in_A[42]
  PIN wd_in_B[42]
    DIRECTION INPUT ;
    USE SIGNAL ;
    SHAPE ABUTMENT ;
    PORT
      LAYER M4 ;
      RECT 93.836 134.352 93.860 134.376 ;
    END
  END wd_in_B[42]
  PIN wd_in_A[43]
    DIRECTION INPUT ;
    USE SIGNAL ;
    SHAPE ABUTMENT ;
    PORT
      LAYER M4 ;
      RECT 0.000 135.120 0.024 135.144 ;
    END
  END wd_in_A[43]
  PIN wd_in_B[43]
    DIRECTION INPUT ;
    USE SIGNAL ;
    SHAPE ABUTMENT ;
    PORT
      LAYER M4 ;
      RECT 93.836 135.120 93.860 135.144 ;
    END
  END wd_in_B[43]
  PIN wd_in_A[44]
    DIRECTION INPUT ;
    USE SIGNAL ;
    SHAPE ABUTMENT ;
    PORT
      LAYER M4 ;
      RECT 0.000 135.888 0.024 135.912 ;
    END
  END wd_in_A[44]
  PIN wd_in_B[44]
    DIRECTION INPUT ;
    USE SIGNAL ;
    SHAPE ABUTMENT ;
    PORT
      LAYER M4 ;
      RECT 93.836 135.888 93.860 135.912 ;
    END
  END wd_in_B[44]
  PIN wd_in_A[45]
    DIRECTION INPUT ;
    USE SIGNAL ;
    SHAPE ABUTMENT ;
    PORT
      LAYER M4 ;
      RECT 0.000 136.656 0.024 136.680 ;
    END
  END wd_in_A[45]
  PIN wd_in_B[45]
    DIRECTION INPUT ;
    USE SIGNAL ;
    SHAPE ABUTMENT ;
    PORT
      LAYER M4 ;
      RECT 93.836 136.656 93.860 136.680 ;
    END
  END wd_in_B[45]
  PIN wd_in_A[46]
    DIRECTION INPUT ;
    USE SIGNAL ;
    SHAPE ABUTMENT ;
    PORT
      LAYER M4 ;
      RECT 0.000 137.424 0.024 137.448 ;
    END
  END wd_in_A[46]
  PIN wd_in_B[46]
    DIRECTION INPUT ;
    USE SIGNAL ;
    SHAPE ABUTMENT ;
    PORT
      LAYER M4 ;
      RECT 93.836 137.424 93.860 137.448 ;
    END
  END wd_in_B[46]
  PIN wd_in_A[47]
    DIRECTION INPUT ;
    USE SIGNAL ;
    SHAPE ABUTMENT ;
    PORT
      LAYER M4 ;
      RECT 0.000 138.192 0.024 138.216 ;
    END
  END wd_in_A[47]
  PIN wd_in_B[47]
    DIRECTION INPUT ;
    USE SIGNAL ;
    SHAPE ABUTMENT ;
    PORT
      LAYER M4 ;
      RECT 93.836 138.192 93.860 138.216 ;
    END
  END wd_in_B[47]
  PIN wd_in_A[48]
    DIRECTION INPUT ;
    USE SIGNAL ;
    SHAPE ABUTMENT ;
    PORT
      LAYER M4 ;
      RECT 0.000 138.960 0.024 138.984 ;
    END
  END wd_in_A[48]
  PIN wd_in_B[48]
    DIRECTION INPUT ;
    USE SIGNAL ;
    SHAPE ABUTMENT ;
    PORT
      LAYER M4 ;
      RECT 93.836 138.960 93.860 138.984 ;
    END
  END wd_in_B[48]
  PIN wd_in_A[49]
    DIRECTION INPUT ;
    USE SIGNAL ;
    SHAPE ABUTMENT ;
    PORT
      LAYER M4 ;
      RECT 0.000 139.728 0.024 139.752 ;
    END
  END wd_in_A[49]
  PIN wd_in_B[49]
    DIRECTION INPUT ;
    USE SIGNAL ;
    SHAPE ABUTMENT ;
    PORT
      LAYER M4 ;
      RECT 93.836 139.728 93.860 139.752 ;
    END
  END wd_in_B[49]
  PIN wd_in_A[50]
    DIRECTION INPUT ;
    USE SIGNAL ;
    SHAPE ABUTMENT ;
    PORT
      LAYER M4 ;
      RECT 0.000 140.496 0.024 140.520 ;
    END
  END wd_in_A[50]
  PIN wd_in_B[50]
    DIRECTION INPUT ;
    USE SIGNAL ;
    SHAPE ABUTMENT ;
    PORT
      LAYER M4 ;
      RECT 93.836 140.496 93.860 140.520 ;
    END
  END wd_in_B[50]
  PIN wd_in_A[51]
    DIRECTION INPUT ;
    USE SIGNAL ;
    SHAPE ABUTMENT ;
    PORT
      LAYER M4 ;
      RECT 0.000 141.264 0.024 141.288 ;
    END
  END wd_in_A[51]
  PIN wd_in_B[51]
    DIRECTION INPUT ;
    USE SIGNAL ;
    SHAPE ABUTMENT ;
    PORT
      LAYER M4 ;
      RECT 93.836 141.264 93.860 141.288 ;
    END
  END wd_in_B[51]
  PIN wd_in_A[52]
    DIRECTION INPUT ;
    USE SIGNAL ;
    SHAPE ABUTMENT ;
    PORT
      LAYER M4 ;
      RECT 0.000 142.032 0.024 142.056 ;
    END
  END wd_in_A[52]
  PIN wd_in_B[52]
    DIRECTION INPUT ;
    USE SIGNAL ;
    SHAPE ABUTMENT ;
    PORT
      LAYER M4 ;
      RECT 93.836 142.032 93.860 142.056 ;
    END
  END wd_in_B[52]
  PIN wd_in_A[53]
    DIRECTION INPUT ;
    USE SIGNAL ;
    SHAPE ABUTMENT ;
    PORT
      LAYER M4 ;
      RECT 0.000 142.800 0.024 142.824 ;
    END
  END wd_in_A[53]
  PIN wd_in_B[53]
    DIRECTION INPUT ;
    USE SIGNAL ;
    SHAPE ABUTMENT ;
    PORT
      LAYER M4 ;
      RECT 93.836 142.800 93.860 142.824 ;
    END
  END wd_in_B[53]
  PIN wd_in_A[54]
    DIRECTION INPUT ;
    USE SIGNAL ;
    SHAPE ABUTMENT ;
    PORT
      LAYER M4 ;
      RECT 0.000 143.568 0.024 143.592 ;
    END
  END wd_in_A[54]
  PIN wd_in_B[54]
    DIRECTION INPUT ;
    USE SIGNAL ;
    SHAPE ABUTMENT ;
    PORT
      LAYER M4 ;
      RECT 93.836 143.568 93.860 143.592 ;
    END
  END wd_in_B[54]
  PIN wd_in_A[55]
    DIRECTION INPUT ;
    USE SIGNAL ;
    SHAPE ABUTMENT ;
    PORT
      LAYER M4 ;
      RECT 0.000 144.336 0.024 144.360 ;
    END
  END wd_in_A[55]
  PIN wd_in_B[55]
    DIRECTION INPUT ;
    USE SIGNAL ;
    SHAPE ABUTMENT ;
    PORT
      LAYER M4 ;
      RECT 93.836 144.336 93.860 144.360 ;
    END
  END wd_in_B[55]
  PIN wd_in_A[56]
    DIRECTION INPUT ;
    USE SIGNAL ;
    SHAPE ABUTMENT ;
    PORT
      LAYER M4 ;
      RECT 0.000 145.104 0.024 145.128 ;
    END
  END wd_in_A[56]
  PIN wd_in_B[56]
    DIRECTION INPUT ;
    USE SIGNAL ;
    SHAPE ABUTMENT ;
    PORT
      LAYER M4 ;
      RECT 93.836 145.104 93.860 145.128 ;
    END
  END wd_in_B[56]
  PIN wd_in_A[57]
    DIRECTION INPUT ;
    USE SIGNAL ;
    SHAPE ABUTMENT ;
    PORT
      LAYER M4 ;
      RECT 0.000 145.872 0.024 145.896 ;
    END
  END wd_in_A[57]
  PIN wd_in_B[57]
    DIRECTION INPUT ;
    USE SIGNAL ;
    SHAPE ABUTMENT ;
    PORT
      LAYER M4 ;
      RECT 93.836 145.872 93.860 145.896 ;
    END
  END wd_in_B[57]
  PIN wd_in_A[58]
    DIRECTION INPUT ;
    USE SIGNAL ;
    SHAPE ABUTMENT ;
    PORT
      LAYER M4 ;
      RECT 0.000 146.640 0.024 146.664 ;
    END
  END wd_in_A[58]
  PIN wd_in_B[58]
    DIRECTION INPUT ;
    USE SIGNAL ;
    SHAPE ABUTMENT ;
    PORT
      LAYER M4 ;
      RECT 93.836 146.640 93.860 146.664 ;
    END
  END wd_in_B[58]
  PIN wd_in_A[59]
    DIRECTION INPUT ;
    USE SIGNAL ;
    SHAPE ABUTMENT ;
    PORT
      LAYER M4 ;
      RECT 0.000 147.408 0.024 147.432 ;
    END
  END wd_in_A[59]
  PIN wd_in_B[59]
    DIRECTION INPUT ;
    USE SIGNAL ;
    SHAPE ABUTMENT ;
    PORT
      LAYER M4 ;
      RECT 93.836 147.408 93.860 147.432 ;
    END
  END wd_in_B[59]
  PIN wd_in_A[60]
    DIRECTION INPUT ;
    USE SIGNAL ;
    SHAPE ABUTMENT ;
    PORT
      LAYER M4 ;
      RECT 0.000 148.176 0.024 148.200 ;
    END
  END wd_in_A[60]
  PIN wd_in_B[60]
    DIRECTION INPUT ;
    USE SIGNAL ;
    SHAPE ABUTMENT ;
    PORT
      LAYER M4 ;
      RECT 93.836 148.176 93.860 148.200 ;
    END
  END wd_in_B[60]
  PIN wd_in_A[61]
    DIRECTION INPUT ;
    USE SIGNAL ;
    SHAPE ABUTMENT ;
    PORT
      LAYER M4 ;
      RECT 0.000 148.944 0.024 148.968 ;
    END
  END wd_in_A[61]
  PIN wd_in_B[61]
    DIRECTION INPUT ;
    USE SIGNAL ;
    SHAPE ABUTMENT ;
    PORT
      LAYER M4 ;
      RECT 93.836 148.944 93.860 148.968 ;
    END
  END wd_in_B[61]
  PIN wd_in_A[62]
    DIRECTION INPUT ;
    USE SIGNAL ;
    SHAPE ABUTMENT ;
    PORT
      LAYER M4 ;
      RECT 0.000 149.712 0.024 149.736 ;
    END
  END wd_in_A[62]
  PIN wd_in_B[62]
    DIRECTION INPUT ;
    USE SIGNAL ;
    SHAPE ABUTMENT ;
    PORT
      LAYER M4 ;
      RECT 93.836 149.712 93.860 149.736 ;
    END
  END wd_in_B[62]
  PIN wd_in_A[63]
    DIRECTION INPUT ;
    USE SIGNAL ;
    SHAPE ABUTMENT ;
    PORT
      LAYER M4 ;
      RECT 0.000 150.480 0.024 150.504 ;
    END
  END wd_in_A[63]
  PIN wd_in_B[63]
    DIRECTION INPUT ;
    USE SIGNAL ;
    SHAPE ABUTMENT ;
    PORT
      LAYER M4 ;
      RECT 93.836 150.480 93.860 150.504 ;
    END
  END wd_in_B[63]
  PIN addr_in_A[0]
    DIRECTION INPUT ;
    USE SIGNAL ;
    SHAPE ABUTMENT ;
    PORT
      LAYER M4 ;
      RECT 0.000 153.120 0.024 153.144 ;
    END
  END addr_in_A[0]
  PIN addr_in_B[0]
    DIRECTION INPUT ;
    USE SIGNAL ;
    SHAPE ABUTMENT ;
    PORT
      LAYER M4 ;
      RECT 93.836 153.120 93.860 153.144 ;
    END
  END addr_in_B[0]
  PIN addr_in_A[1]
    DIRECTION INPUT ;
    USE SIGNAL ;
    SHAPE ABUTMENT ;
    PORT
      LAYER M4 ;
      RECT 0.000 153.888 0.024 153.912 ;
    END
  END addr_in_A[1]
  PIN addr_in_B[1]
    DIRECTION INPUT ;
    USE SIGNAL ;
    SHAPE ABUTMENT ;
    PORT
      LAYER M4 ;
      RECT 93.836 153.888 93.860 153.912 ;
    END
  END addr_in_B[1]
  PIN addr_in_A[2]
    DIRECTION INPUT ;
    USE SIGNAL ;
    SHAPE ABUTMENT ;
    PORT
      LAYER M4 ;
      RECT 0.000 154.656 0.024 154.680 ;
    END
  END addr_in_A[2]
  PIN addr_in_B[2]
    DIRECTION INPUT ;
    USE SIGNAL ;
    SHAPE ABUTMENT ;
    PORT
      LAYER M4 ;
      RECT 93.836 154.656 93.860 154.680 ;
    END
  END addr_in_B[2]
  PIN addr_in_A[3]
    DIRECTION INPUT ;
    USE SIGNAL ;
    SHAPE ABUTMENT ;
    PORT
      LAYER M4 ;
      RECT 0.000 155.424 0.024 155.448 ;
    END
  END addr_in_A[3]
  PIN addr_in_B[3]
    DIRECTION INPUT ;
    USE SIGNAL ;
    SHAPE ABUTMENT ;
    PORT
      LAYER M4 ;
      RECT 93.836 155.424 93.860 155.448 ;
    END
  END addr_in_B[3]
  PIN addr_in_A[4]
    DIRECTION INPUT ;
    USE SIGNAL ;
    SHAPE ABUTMENT ;
    PORT
      LAYER M4 ;
      RECT 0.000 156.192 0.024 156.216 ;
    END
  END addr_in_A[4]
  PIN addr_in_B[4]
    DIRECTION INPUT ;
    USE SIGNAL ;
    SHAPE ABUTMENT ;
    PORT
      LAYER M4 ;
      RECT 93.836 156.192 93.860 156.216 ;
    END
  END addr_in_B[4]
  PIN addr_in_A[5]
    DIRECTION INPUT ;
    USE SIGNAL ;
    SHAPE ABUTMENT ;
    PORT
      LAYER M4 ;
      RECT 0.000 156.960 0.024 156.984 ;
    END
  END addr_in_A[5]
  PIN addr_in_B[5]
    DIRECTION INPUT ;
    USE SIGNAL ;
    SHAPE ABUTMENT ;
    PORT
      LAYER M4 ;
      RECT 93.836 156.960 93.860 156.984 ;
    END
  END addr_in_B[5]
  PIN addr_in_A[6]
    DIRECTION INPUT ;
    USE SIGNAL ;
    SHAPE ABUTMENT ;
    PORT
      LAYER M4 ;
      RECT 0.000 157.728 0.024 157.752 ;
    END
  END addr_in_A[6]
  PIN addr_in_B[6]
    DIRECTION INPUT ;
    USE SIGNAL ;
    SHAPE ABUTMENT ;
    PORT
      LAYER M4 ;
      RECT 93.836 157.728 93.860 157.752 ;
    END
  END addr_in_B[6]
  PIN addr_in_A[7]
    DIRECTION INPUT ;
    USE SIGNAL ;
    SHAPE ABUTMENT ;
    PORT
      LAYER M4 ;
      RECT 0.000 158.496 0.024 158.520 ;
    END
  END addr_in_A[7]
  PIN addr_in_B[7]
    DIRECTION INPUT ;
    USE SIGNAL ;
    SHAPE ABUTMENT ;
    PORT
      LAYER M4 ;
      RECT 93.836 158.496 93.860 158.520 ;
    END
  END addr_in_B[7]
  PIN addr_in_A[8]
    DIRECTION INPUT ;
    USE SIGNAL ;
    SHAPE ABUTMENT ;
    PORT
      LAYER M4 ;
      RECT 0.000 159.264 0.024 159.288 ;
    END
  END addr_in_A[8]
  PIN addr_in_B[8]
    DIRECTION INPUT ;
    USE SIGNAL ;
    SHAPE ABUTMENT ;
    PORT
      LAYER M4 ;
      RECT 93.836 159.264 93.860 159.288 ;
    END
  END addr_in_B[8]
  PIN addr_in_A[9]
    DIRECTION INPUT ;
    USE SIGNAL ;
    SHAPE ABUTMENT ;
    PORT
      LAYER M4 ;
      RECT 0.000 160.032 0.024 160.056 ;
    END
  END addr_in_A[9]
  PIN addr_in_B[9]
    DIRECTION INPUT ;
    USE SIGNAL ;
    SHAPE ABUTMENT ;
    PORT
      LAYER M4 ;
      RECT 93.836 160.032 93.860 160.056 ;
    END
  END addr_in_B[9]
  PIN addr_in_A[10]
    DIRECTION INPUT ;
    USE SIGNAL ;
    SHAPE ABUTMENT ;
    PORT
      LAYER M4 ;
      RECT 0.000 160.800 0.024 160.824 ;
    END
  END addr_in_A[10]
  PIN addr_in_B[10]
    DIRECTION INPUT ;
    USE SIGNAL ;
    SHAPE ABUTMENT ;
    PORT
      LAYER M4 ;
      RECT 93.836 160.800 93.860 160.824 ;
    END
  END addr_in_B[10]
  PIN addr_in_A[11]
    DIRECTION INPUT ;
    USE SIGNAL ;
    SHAPE ABUTMENT ;
    PORT
      LAYER M4 ;
      RECT 0.000 161.568 0.024 161.592 ;
    END
  END addr_in_A[11]
  PIN addr_in_B[11]
    DIRECTION INPUT ;
    USE SIGNAL ;
    SHAPE ABUTMENT ;
    PORT
      LAYER M4 ;
      RECT 93.836 161.568 93.860 161.592 ;
    END
  END addr_in_B[11]
  PIN we_in_A
    DIRECTION INPUT ;
    USE SIGNAL ;
    SHAPE ABUTMENT ;
    PORT
      LAYER M4 ;
      RECT 0.000 164.208 0.024 164.232 ;
    END
  END we_in_A
  PIN we_in_B
    DIRECTION INPUT ;
    USE SIGNAL ;
    SHAPE ABUTMENT ;
    PORT
      LAYER M4 ;
      RECT 93.836 164.208 93.860 164.232 ;
    END
  END we_in_B
  PIN ce_in
    DIRECTION INPUT ;
    USE SIGNAL ;
    SHAPE ABUTMENT ;
    PORT
      LAYER M4 ;
      RECT 0.000 164.976 0.024 165.000 ;
    END
  END ce_in
  PIN clk
    DIRECTION INPUT ;
    USE SIGNAL ;
    SHAPE ABUTMENT ;
    PORT
      LAYER M4 ;
      RECT 0.000 165.744 0.024 165.768 ;
    END
  END clk
  PIN VSS
    DIRECTION INOUT ;
    USE GROUND ;
    PORT
      LAYER M4 ;
      RECT 0.048 0.000 93.812 0.096 ;
      RECT 0.048 0.768 93.812 0.864 ;
      RECT 0.048 1.536 93.812 1.632 ;
      RECT 0.048 2.304 93.812 2.400 ;
      RECT 0.048 3.072 93.812 3.168 ;
      RECT 0.048 3.840 93.812 3.936 ;
      RECT 0.048 4.608 93.812 4.704 ;
      RECT 0.048 5.376 93.812 5.472 ;
      RECT 0.048 6.144 93.812 6.240 ;
      RECT 0.048 6.912 93.812 7.008 ;
      RECT 0.048 7.680 93.812 7.776 ;
      RECT 0.048 8.448 93.812 8.544 ;
      RECT 0.048 9.216 93.812 9.312 ;
      RECT 0.048 9.984 93.812 10.080 ;
      RECT 0.048 10.752 93.812 10.848 ;
      RECT 0.048 11.520 93.812 11.616 ;
      RECT 0.048 12.288 93.812 12.384 ;
      RECT 0.048 13.056 93.812 13.152 ;
      RECT 0.048 13.824 93.812 13.920 ;
      RECT 0.048 14.592 93.812 14.688 ;
      RECT 0.048 15.360 93.812 15.456 ;
      RECT 0.048 16.128 93.812 16.224 ;
      RECT 0.048 16.896 93.812 16.992 ;
      RECT 0.048 17.664 93.812 17.760 ;
      RECT 0.048 18.432 93.812 18.528 ;
      RECT 0.048 19.200 93.812 19.296 ;
      RECT 0.048 19.968 93.812 20.064 ;
      RECT 0.048 20.736 93.812 20.832 ;
      RECT 0.048 21.504 93.812 21.600 ;
      RECT 0.048 22.272 93.812 22.368 ;
      RECT 0.048 23.040 93.812 23.136 ;
      RECT 0.048 23.808 93.812 23.904 ;
      RECT 0.048 24.576 93.812 24.672 ;
      RECT 0.048 25.344 93.812 25.440 ;
      RECT 0.048 26.112 93.812 26.208 ;
      RECT 0.048 26.880 93.812 26.976 ;
      RECT 0.048 27.648 93.812 27.744 ;
      RECT 0.048 28.416 93.812 28.512 ;
      RECT 0.048 29.184 93.812 29.280 ;
      RECT 0.048 29.952 93.812 30.048 ;
      RECT 0.048 30.720 93.812 30.816 ;
      RECT 0.048 31.488 93.812 31.584 ;
      RECT 0.048 32.256 93.812 32.352 ;
      RECT 0.048 33.024 93.812 33.120 ;
      RECT 0.048 33.792 93.812 33.888 ;
      RECT 0.048 34.560 93.812 34.656 ;
      RECT 0.048 35.328 93.812 35.424 ;
      RECT 0.048 36.096 93.812 36.192 ;
      RECT 0.048 36.864 93.812 36.960 ;
      RECT 0.048 37.632 93.812 37.728 ;
      RECT 0.048 38.400 93.812 38.496 ;
      RECT 0.048 39.168 93.812 39.264 ;
      RECT 0.048 39.936 93.812 40.032 ;
      RECT 0.048 40.704 93.812 40.800 ;
      RECT 0.048 41.472 93.812 41.568 ;
      RECT 0.048 42.240 93.812 42.336 ;
      RECT 0.048 43.008 93.812 43.104 ;
      RECT 0.048 43.776 93.812 43.872 ;
      RECT 0.048 44.544 93.812 44.640 ;
      RECT 0.048 45.312 93.812 45.408 ;
      RECT 0.048 46.080 93.812 46.176 ;
      RECT 0.048 46.848 93.812 46.944 ;
      RECT 0.048 47.616 93.812 47.712 ;
      RECT 0.048 48.384 93.812 48.480 ;
      RECT 0.048 49.152 93.812 49.248 ;
      RECT 0.048 49.920 93.812 50.016 ;
      RECT 0.048 50.688 93.812 50.784 ;
      RECT 0.048 51.456 93.812 51.552 ;
      RECT 0.048 52.224 93.812 52.320 ;
      RECT 0.048 52.992 93.812 53.088 ;
      RECT 0.048 53.760 93.812 53.856 ;
      RECT 0.048 54.528 93.812 54.624 ;
      RECT 0.048 55.296 93.812 55.392 ;
      RECT 0.048 56.064 93.812 56.160 ;
      RECT 0.048 56.832 93.812 56.928 ;
      RECT 0.048 57.600 93.812 57.696 ;
      RECT 0.048 58.368 93.812 58.464 ;
      RECT 0.048 59.136 93.812 59.232 ;
      RECT 0.048 59.904 93.812 60.000 ;
      RECT 0.048 60.672 93.812 60.768 ;
      RECT 0.048 61.440 93.812 61.536 ;
      RECT 0.048 62.208 93.812 62.304 ;
      RECT 0.048 62.976 93.812 63.072 ;
      RECT 0.048 63.744 93.812 63.840 ;
      RECT 0.048 64.512 93.812 64.608 ;
      RECT 0.048 65.280 93.812 65.376 ;
      RECT 0.048 66.048 93.812 66.144 ;
      RECT 0.048 66.816 93.812 66.912 ;
      RECT 0.048 67.584 93.812 67.680 ;
      RECT 0.048 68.352 93.812 68.448 ;
      RECT 0.048 69.120 93.812 69.216 ;
      RECT 0.048 69.888 93.812 69.984 ;
      RECT 0.048 70.656 93.812 70.752 ;
      RECT 0.048 71.424 93.812 71.520 ;
      RECT 0.048 72.192 93.812 72.288 ;
      RECT 0.048 72.960 93.812 73.056 ;
      RECT 0.048 73.728 93.812 73.824 ;
      RECT 0.048 74.496 93.812 74.592 ;
      RECT 0.048 75.264 93.812 75.360 ;
      RECT 0.048 76.032 93.812 76.128 ;
      RECT 0.048 76.800 93.812 76.896 ;
      RECT 0.048 77.568 93.812 77.664 ;
      RECT 0.048 78.336 93.812 78.432 ;
      RECT 0.048 79.104 93.812 79.200 ;
      RECT 0.048 79.872 93.812 79.968 ;
      RECT 0.048 80.640 93.812 80.736 ;
      RECT 0.048 81.408 93.812 81.504 ;
      RECT 0.048 82.176 93.812 82.272 ;
      RECT 0.048 82.944 93.812 83.040 ;
      RECT 0.048 83.712 93.812 83.808 ;
      RECT 0.048 84.480 93.812 84.576 ;
      RECT 0.048 85.248 93.812 85.344 ;
      RECT 0.048 86.016 93.812 86.112 ;
      RECT 0.048 86.784 93.812 86.880 ;
      RECT 0.048 87.552 93.812 87.648 ;
      RECT 0.048 88.320 93.812 88.416 ;
      RECT 0.048 89.088 93.812 89.184 ;
      RECT 0.048 89.856 93.812 89.952 ;
      RECT 0.048 90.624 93.812 90.720 ;
      RECT 0.048 91.392 93.812 91.488 ;
      RECT 0.048 92.160 93.812 92.256 ;
      RECT 0.048 92.928 93.812 93.024 ;
      RECT 0.048 93.696 93.812 93.792 ;
      RECT 0.048 94.464 93.812 94.560 ;
      RECT 0.048 95.232 93.812 95.328 ;
      RECT 0.048 96.000 93.812 96.096 ;
      RECT 0.048 96.768 93.812 96.864 ;
      RECT 0.048 97.536 93.812 97.632 ;
      RECT 0.048 98.304 93.812 98.400 ;
      RECT 0.048 99.072 93.812 99.168 ;
      RECT 0.048 99.840 93.812 99.936 ;
      RECT 0.048 100.608 93.812 100.704 ;
      RECT 0.048 101.376 93.812 101.472 ;
      RECT 0.048 102.144 93.812 102.240 ;
      RECT 0.048 102.912 93.812 103.008 ;
      RECT 0.048 103.680 93.812 103.776 ;
      RECT 0.048 104.448 93.812 104.544 ;
      RECT 0.048 105.216 93.812 105.312 ;
      RECT 0.048 105.984 93.812 106.080 ;
      RECT 0.048 106.752 93.812 106.848 ;
      RECT 0.048 107.520 93.812 107.616 ;
      RECT 0.048 108.288 93.812 108.384 ;
      RECT 0.048 109.056 93.812 109.152 ;
      RECT 0.048 109.824 93.812 109.920 ;
      RECT 0.048 110.592 93.812 110.688 ;
      RECT 0.048 111.360 93.812 111.456 ;
      RECT 0.048 112.128 93.812 112.224 ;
      RECT 0.048 112.896 93.812 112.992 ;
      RECT 0.048 113.664 93.812 113.760 ;
      RECT 0.048 114.432 93.812 114.528 ;
      RECT 0.048 115.200 93.812 115.296 ;
      RECT 0.048 115.968 93.812 116.064 ;
      RECT 0.048 116.736 93.812 116.832 ;
      RECT 0.048 117.504 93.812 117.600 ;
      RECT 0.048 118.272 93.812 118.368 ;
      RECT 0.048 119.040 93.812 119.136 ;
      RECT 0.048 119.808 93.812 119.904 ;
      RECT 0.048 120.576 93.812 120.672 ;
      RECT 0.048 121.344 93.812 121.440 ;
      RECT 0.048 122.112 93.812 122.208 ;
      RECT 0.048 122.880 93.812 122.976 ;
      RECT 0.048 123.648 93.812 123.744 ;
      RECT 0.048 124.416 93.812 124.512 ;
      RECT 0.048 125.184 93.812 125.280 ;
      RECT 0.048 125.952 93.812 126.048 ;
      RECT 0.048 126.720 93.812 126.816 ;
      RECT 0.048 127.488 93.812 127.584 ;
      RECT 0.048 128.256 93.812 128.352 ;
      RECT 0.048 129.024 93.812 129.120 ;
      RECT 0.048 129.792 93.812 129.888 ;
      RECT 0.048 130.560 93.812 130.656 ;
      RECT 0.048 131.328 93.812 131.424 ;
      RECT 0.048 132.096 93.812 132.192 ;
      RECT 0.048 132.864 93.812 132.960 ;
      RECT 0.048 133.632 93.812 133.728 ;
      RECT 0.048 134.400 93.812 134.496 ;
      RECT 0.048 135.168 93.812 135.264 ;
      RECT 0.048 135.936 93.812 136.032 ;
      RECT 0.048 136.704 93.812 136.800 ;
      RECT 0.048 137.472 93.812 137.568 ;
      RECT 0.048 138.240 93.812 138.336 ;
      RECT 0.048 139.008 93.812 139.104 ;
      RECT 0.048 139.776 93.812 139.872 ;
      RECT 0.048 140.544 93.812 140.640 ;
      RECT 0.048 141.312 93.812 141.408 ;
      RECT 0.048 142.080 93.812 142.176 ;
      RECT 0.048 142.848 93.812 142.944 ;
      RECT 0.048 143.616 93.812 143.712 ;
      RECT 0.048 144.384 93.812 144.480 ;
      RECT 0.048 145.152 93.812 145.248 ;
      RECT 0.048 145.920 93.812 146.016 ;
      RECT 0.048 146.688 93.812 146.784 ;
      RECT 0.048 147.456 93.812 147.552 ;
      RECT 0.048 148.224 93.812 148.320 ;
      RECT 0.048 148.992 93.812 149.088 ;
      RECT 0.048 149.760 93.812 149.856 ;
      RECT 0.048 150.528 93.812 150.624 ;
      RECT 0.048 151.296 93.812 151.392 ;
      RECT 0.048 152.064 93.812 152.160 ;
      RECT 0.048 152.832 93.812 152.928 ;
      RECT 0.048 153.600 93.812 153.696 ;
      RECT 0.048 154.368 93.812 154.464 ;
      RECT 0.048 155.136 93.812 155.232 ;
      RECT 0.048 155.904 93.812 156.000 ;
      RECT 0.048 156.672 93.812 156.768 ;
      RECT 0.048 157.440 93.812 157.536 ;
      RECT 0.048 158.208 93.812 158.304 ;
      RECT 0.048 158.976 93.812 159.072 ;
      RECT 0.048 159.744 93.812 159.840 ;
      RECT 0.048 160.512 93.812 160.608 ;
      RECT 0.048 161.280 93.812 161.376 ;
      RECT 0.048 162.048 93.812 162.144 ;
      RECT 0.048 162.816 93.812 162.912 ;
      RECT 0.048 163.584 93.812 163.680 ;
      RECT 0.048 164.352 93.812 164.448 ;
      RECT 0.048 165.120 93.812 165.216 ;
      RECT 0.048 165.888 93.812 165.984 ;
    END
  END VSS
  PIN VDD
    DIRECTION INOUT ;
    USE POWER ;
    PORT
      LAYER M4 ;
      RECT 0.048 0.384 93.812 0.480 ;
      RECT 0.048 1.152 93.812 1.248 ;
      RECT 0.048 1.920 93.812 2.016 ;
      RECT 0.048 2.688 93.812 2.784 ;
      RECT 0.048 3.456 93.812 3.552 ;
      RECT 0.048 4.224 93.812 4.320 ;
      RECT 0.048 4.992 93.812 5.088 ;
      RECT 0.048 5.760 93.812 5.856 ;
      RECT 0.048 6.528 93.812 6.624 ;
      RECT 0.048 7.296 93.812 7.392 ;
      RECT 0.048 8.064 93.812 8.160 ;
      RECT 0.048 8.832 93.812 8.928 ;
      RECT 0.048 9.600 93.812 9.696 ;
      RECT 0.048 10.368 93.812 10.464 ;
      RECT 0.048 11.136 93.812 11.232 ;
      RECT 0.048 11.904 93.812 12.000 ;
      RECT 0.048 12.672 93.812 12.768 ;
      RECT 0.048 13.440 93.812 13.536 ;
      RECT 0.048 14.208 93.812 14.304 ;
      RECT 0.048 14.976 93.812 15.072 ;
      RECT 0.048 15.744 93.812 15.840 ;
      RECT 0.048 16.512 93.812 16.608 ;
      RECT 0.048 17.280 93.812 17.376 ;
      RECT 0.048 18.048 93.812 18.144 ;
      RECT 0.048 18.816 93.812 18.912 ;
      RECT 0.048 19.584 93.812 19.680 ;
      RECT 0.048 20.352 93.812 20.448 ;
      RECT 0.048 21.120 93.812 21.216 ;
      RECT 0.048 21.888 93.812 21.984 ;
      RECT 0.048 22.656 93.812 22.752 ;
      RECT 0.048 23.424 93.812 23.520 ;
      RECT 0.048 24.192 93.812 24.288 ;
      RECT 0.048 24.960 93.812 25.056 ;
      RECT 0.048 25.728 93.812 25.824 ;
      RECT 0.048 26.496 93.812 26.592 ;
      RECT 0.048 27.264 93.812 27.360 ;
      RECT 0.048 28.032 93.812 28.128 ;
      RECT 0.048 28.800 93.812 28.896 ;
      RECT 0.048 29.568 93.812 29.664 ;
      RECT 0.048 30.336 93.812 30.432 ;
      RECT 0.048 31.104 93.812 31.200 ;
      RECT 0.048 31.872 93.812 31.968 ;
      RECT 0.048 32.640 93.812 32.736 ;
      RECT 0.048 33.408 93.812 33.504 ;
      RECT 0.048 34.176 93.812 34.272 ;
      RECT 0.048 34.944 93.812 35.040 ;
      RECT 0.048 35.712 93.812 35.808 ;
      RECT 0.048 36.480 93.812 36.576 ;
      RECT 0.048 37.248 93.812 37.344 ;
      RECT 0.048 38.016 93.812 38.112 ;
      RECT 0.048 38.784 93.812 38.880 ;
      RECT 0.048 39.552 93.812 39.648 ;
      RECT 0.048 40.320 93.812 40.416 ;
      RECT 0.048 41.088 93.812 41.184 ;
      RECT 0.048 41.856 93.812 41.952 ;
      RECT 0.048 42.624 93.812 42.720 ;
      RECT 0.048 43.392 93.812 43.488 ;
      RECT 0.048 44.160 93.812 44.256 ;
      RECT 0.048 44.928 93.812 45.024 ;
      RECT 0.048 45.696 93.812 45.792 ;
      RECT 0.048 46.464 93.812 46.560 ;
      RECT 0.048 47.232 93.812 47.328 ;
      RECT 0.048 48.000 93.812 48.096 ;
      RECT 0.048 48.768 93.812 48.864 ;
      RECT 0.048 49.536 93.812 49.632 ;
      RECT 0.048 50.304 93.812 50.400 ;
      RECT 0.048 51.072 93.812 51.168 ;
      RECT 0.048 51.840 93.812 51.936 ;
      RECT 0.048 52.608 93.812 52.704 ;
      RECT 0.048 53.376 93.812 53.472 ;
      RECT 0.048 54.144 93.812 54.240 ;
      RECT 0.048 54.912 93.812 55.008 ;
      RECT 0.048 55.680 93.812 55.776 ;
      RECT 0.048 56.448 93.812 56.544 ;
      RECT 0.048 57.216 93.812 57.312 ;
      RECT 0.048 57.984 93.812 58.080 ;
      RECT 0.048 58.752 93.812 58.848 ;
      RECT 0.048 59.520 93.812 59.616 ;
      RECT 0.048 60.288 93.812 60.384 ;
      RECT 0.048 61.056 93.812 61.152 ;
      RECT 0.048 61.824 93.812 61.920 ;
      RECT 0.048 62.592 93.812 62.688 ;
      RECT 0.048 63.360 93.812 63.456 ;
      RECT 0.048 64.128 93.812 64.224 ;
      RECT 0.048 64.896 93.812 64.992 ;
      RECT 0.048 65.664 93.812 65.760 ;
      RECT 0.048 66.432 93.812 66.528 ;
      RECT 0.048 67.200 93.812 67.296 ;
      RECT 0.048 67.968 93.812 68.064 ;
      RECT 0.048 68.736 93.812 68.832 ;
      RECT 0.048 69.504 93.812 69.600 ;
      RECT 0.048 70.272 93.812 70.368 ;
      RECT 0.048 71.040 93.812 71.136 ;
      RECT 0.048 71.808 93.812 71.904 ;
      RECT 0.048 72.576 93.812 72.672 ;
      RECT 0.048 73.344 93.812 73.440 ;
      RECT 0.048 74.112 93.812 74.208 ;
      RECT 0.048 74.880 93.812 74.976 ;
      RECT 0.048 75.648 93.812 75.744 ;
      RECT 0.048 76.416 93.812 76.512 ;
      RECT 0.048 77.184 93.812 77.280 ;
      RECT 0.048 77.952 93.812 78.048 ;
      RECT 0.048 78.720 93.812 78.816 ;
      RECT 0.048 79.488 93.812 79.584 ;
      RECT 0.048 80.256 93.812 80.352 ;
      RECT 0.048 81.024 93.812 81.120 ;
      RECT 0.048 81.792 93.812 81.888 ;
      RECT 0.048 82.560 93.812 82.656 ;
      RECT 0.048 83.328 93.812 83.424 ;
      RECT 0.048 84.096 93.812 84.192 ;
      RECT 0.048 84.864 93.812 84.960 ;
      RECT 0.048 85.632 93.812 85.728 ;
      RECT 0.048 86.400 93.812 86.496 ;
      RECT 0.048 87.168 93.812 87.264 ;
      RECT 0.048 87.936 93.812 88.032 ;
      RECT 0.048 88.704 93.812 88.800 ;
      RECT 0.048 89.472 93.812 89.568 ;
      RECT 0.048 90.240 93.812 90.336 ;
      RECT 0.048 91.008 93.812 91.104 ;
      RECT 0.048 91.776 93.812 91.872 ;
      RECT 0.048 92.544 93.812 92.640 ;
      RECT 0.048 93.312 93.812 93.408 ;
      RECT 0.048 94.080 93.812 94.176 ;
      RECT 0.048 94.848 93.812 94.944 ;
      RECT 0.048 95.616 93.812 95.712 ;
      RECT 0.048 96.384 93.812 96.480 ;
      RECT 0.048 97.152 93.812 97.248 ;
      RECT 0.048 97.920 93.812 98.016 ;
      RECT 0.048 98.688 93.812 98.784 ;
      RECT 0.048 99.456 93.812 99.552 ;
      RECT 0.048 100.224 93.812 100.320 ;
      RECT 0.048 100.992 93.812 101.088 ;
      RECT 0.048 101.760 93.812 101.856 ;
      RECT 0.048 102.528 93.812 102.624 ;
      RECT 0.048 103.296 93.812 103.392 ;
      RECT 0.048 104.064 93.812 104.160 ;
      RECT 0.048 104.832 93.812 104.928 ;
      RECT 0.048 105.600 93.812 105.696 ;
      RECT 0.048 106.368 93.812 106.464 ;
      RECT 0.048 107.136 93.812 107.232 ;
      RECT 0.048 107.904 93.812 108.000 ;
      RECT 0.048 108.672 93.812 108.768 ;
      RECT 0.048 109.440 93.812 109.536 ;
      RECT 0.048 110.208 93.812 110.304 ;
      RECT 0.048 110.976 93.812 111.072 ;
      RECT 0.048 111.744 93.812 111.840 ;
      RECT 0.048 112.512 93.812 112.608 ;
      RECT 0.048 113.280 93.812 113.376 ;
      RECT 0.048 114.048 93.812 114.144 ;
      RECT 0.048 114.816 93.812 114.912 ;
      RECT 0.048 115.584 93.812 115.680 ;
      RECT 0.048 116.352 93.812 116.448 ;
      RECT 0.048 117.120 93.812 117.216 ;
      RECT 0.048 117.888 93.812 117.984 ;
      RECT 0.048 118.656 93.812 118.752 ;
      RECT 0.048 119.424 93.812 119.520 ;
      RECT 0.048 120.192 93.812 120.288 ;
      RECT 0.048 120.960 93.812 121.056 ;
      RECT 0.048 121.728 93.812 121.824 ;
      RECT 0.048 122.496 93.812 122.592 ;
      RECT 0.048 123.264 93.812 123.360 ;
      RECT 0.048 124.032 93.812 124.128 ;
      RECT 0.048 124.800 93.812 124.896 ;
      RECT 0.048 125.568 93.812 125.664 ;
      RECT 0.048 126.336 93.812 126.432 ;
      RECT 0.048 127.104 93.812 127.200 ;
      RECT 0.048 127.872 93.812 127.968 ;
      RECT 0.048 128.640 93.812 128.736 ;
      RECT 0.048 129.408 93.812 129.504 ;
      RECT 0.048 130.176 93.812 130.272 ;
      RECT 0.048 130.944 93.812 131.040 ;
      RECT 0.048 131.712 93.812 131.808 ;
      RECT 0.048 132.480 93.812 132.576 ;
      RECT 0.048 133.248 93.812 133.344 ;
      RECT 0.048 134.016 93.812 134.112 ;
      RECT 0.048 134.784 93.812 134.880 ;
      RECT 0.048 135.552 93.812 135.648 ;
      RECT 0.048 136.320 93.812 136.416 ;
      RECT 0.048 137.088 93.812 137.184 ;
      RECT 0.048 137.856 93.812 137.952 ;
      RECT 0.048 138.624 93.812 138.720 ;
      RECT 0.048 139.392 93.812 139.488 ;
      RECT 0.048 140.160 93.812 140.256 ;
      RECT 0.048 140.928 93.812 141.024 ;
      RECT 0.048 141.696 93.812 141.792 ;
      RECT 0.048 142.464 93.812 142.560 ;
      RECT 0.048 143.232 93.812 143.328 ;
      RECT 0.048 144.000 93.812 144.096 ;
      RECT 0.048 144.768 93.812 144.864 ;
      RECT 0.048 145.536 93.812 145.632 ;
      RECT 0.048 146.304 93.812 146.400 ;
      RECT 0.048 147.072 93.812 147.168 ;
      RECT 0.048 147.840 93.812 147.936 ;
      RECT 0.048 148.608 93.812 148.704 ;
      RECT 0.048 149.376 93.812 149.472 ;
      RECT 0.048 150.144 93.812 150.240 ;
      RECT 0.048 150.912 93.812 151.008 ;
      RECT 0.048 151.680 93.812 151.776 ;
      RECT 0.048 152.448 93.812 152.544 ;
      RECT 0.048 153.216 93.812 153.312 ;
      RECT 0.048 153.984 93.812 154.080 ;
      RECT 0.048 154.752 93.812 154.848 ;
      RECT 0.048 155.520 93.812 155.616 ;
      RECT 0.048 156.288 93.812 156.384 ;
      RECT 0.048 157.056 93.812 157.152 ;
      RECT 0.048 157.824 93.812 157.920 ;
      RECT 0.048 158.592 93.812 158.688 ;
      RECT 0.048 159.360 93.812 159.456 ;
      RECT 0.048 160.128 93.812 160.224 ;
      RECT 0.048 160.896 93.812 160.992 ;
      RECT 0.048 161.664 93.812 161.760 ;
      RECT 0.048 162.432 93.812 162.528 ;
      RECT 0.048 163.200 93.812 163.296 ;
      RECT 0.048 163.968 93.812 164.064 ;
      RECT 0.048 164.736 93.812 164.832 ;
      RECT 0.048 165.504 93.812 165.600 ;
      RECT 0.048 166.272 93.812 166.368 ;
    END
  END VDD
  OBS
    LAYER M1 ;
    RECT 0 0 93.860 166.600 ;
    LAYER M2 ;
    RECT 0 0 93.860 166.600 ;
    LAYER M3 ;
    RECT 0 0 93.860 166.600 ;
    LAYER M4 ;
    RECT 0 0 93.860 166.600 ;
  END
END fakeram7_dp_4096x64

END LIBRARY
